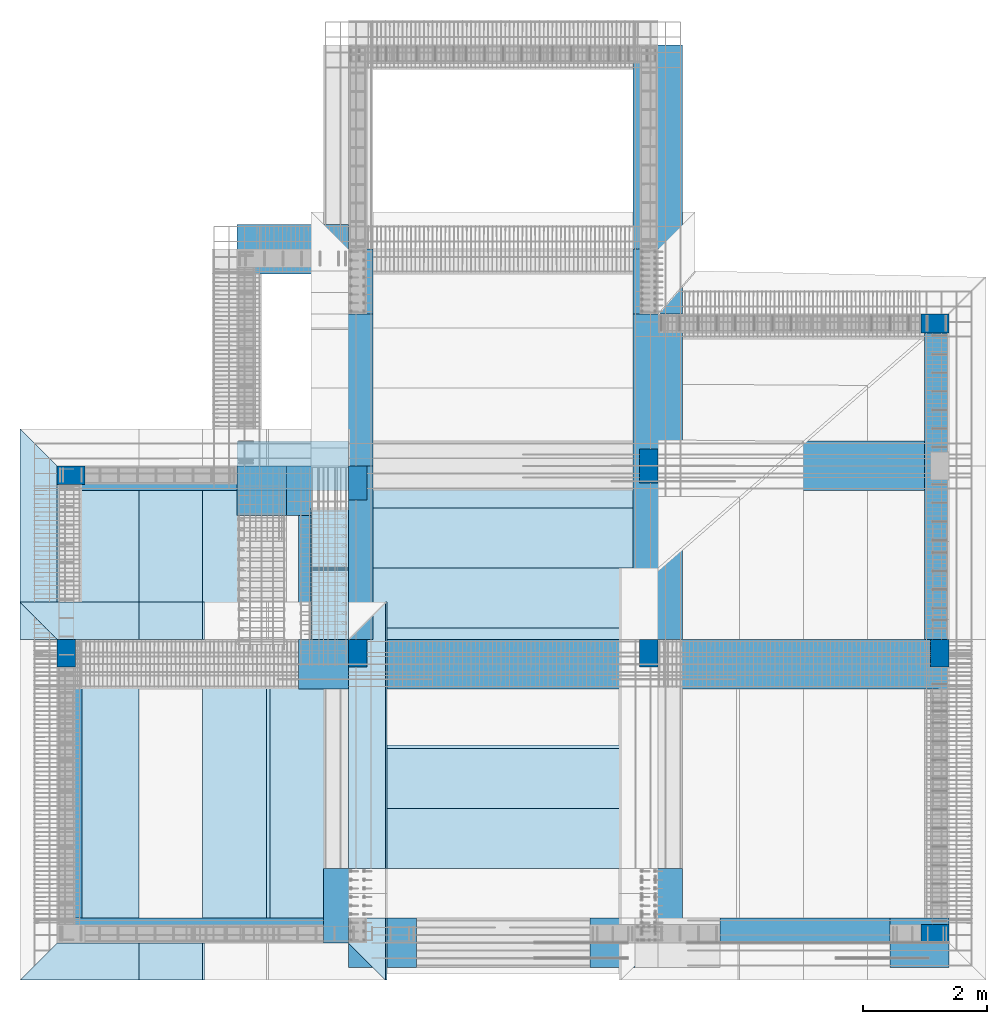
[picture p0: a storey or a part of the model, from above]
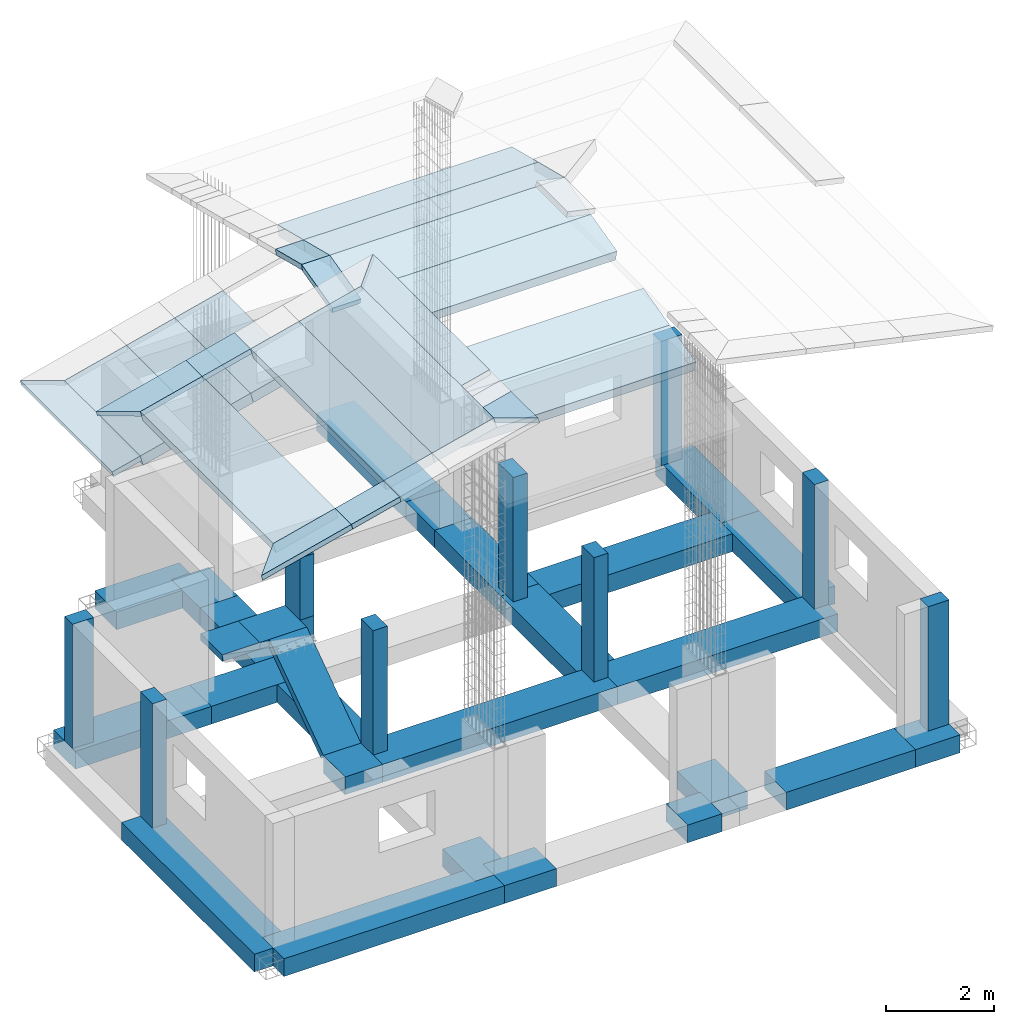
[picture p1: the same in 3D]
Properties of the parts of a building model (IFC4), part 1 of 3

# File
Description: ViewDefinition [CoordinationView]
Made in: IFC file generated by ModeSt (Tecnisoft s.a.s.)

# IfcBuildingStorey (3)
In: Bifamiliare
Name | Elevation (m)
Storey 0 | 0
Storey 1 | 2.8
Storey 2 | 5.95

# IfcBeam: 1 Tr 30x24 (11)
Type - PredefinedType: BEAM; Material: Calcestruzzo
Description: 1 Tr 30x24 - Cemento armato
Pset_BeamCommon - LoadBearing: yes
BaseQuantities - ?: 0.072 m2
Name | In | BaseQuantities, ? (m3) | BaseQuantities, ? (m)
115 | Storey 1 | 0.36 | 5
106 | Storey 1 | 0.3384 | 4.7
106 | Storey 1 | 0.36 | 5
110 | Storey 1 | 0.3384 | 4.7
110 | Storey 1 | 0.36 | 5
120 | Storey 1 | 0.2016 | 2.8
220 | Storey 2 | 0.2016 | 2.8
206 | Storey 2 | 0.3384 | 4.7
206 | Storey 2 | 0.36 | 5
210 | Storey 2 | 0.3384 | 4.7
210 | Storey 2 | 0.36 | 5

# IfcBeam: 10 Scala (6)
Type - PredefinedType: BEAM; Material: Calcestruzzo
Description: 10 Scala - Cemento armato
Pset_BeamCommon - LoadBearing: yes
BaseQuantities - ?: 0.12 m2
Name | In | BaseQuantities, ? (m3) | BaseQuantities, ? (m)
601 | Storey 0 | 0.292957 | 2.44131
602 | Storey 0 | 0.292957 | 2.44131
602 | Storey 0 | 0.096 | 0.8
604 | Storey 1 | 0.096 | 0.8
604 | Storey 1 | 0.305485 | 2.54571
603 | Storey 1 | 0.305485 | 2.54571

# IfcBeam: 11 Pianerottolo (2)
Type - PredefinedType: BEAM; Material: Calcestruzzo
Description: 11 Pianerottolo - Cemento armato
Pset_BeamCommon - LoadBearing: yes
BaseQuantities - ?: 0.15 m2; ?: 0.12 m3; ?: 0.8 m
Name | In
601 | Storey 0
603 | Storey 1

# IfcBeam: 2 Tr 40x24, 102
In: Storey 1
Type - PredefinedType: BEAM; Material: Calcestruzzo
Description: 2 Tr 40x24 - Cemento armato
Pset_BeamCommon - LoadBearing: yes
BaseQuantities - ?: 0.096 m2; ?: 0.48 m3; ?: 5 m

# IfcBeam: 3 Tr 30x44 (34)
Type - PredefinedType: BEAM; Material: Calcestruzzo
Description: 3 Tr 30x44 - Cemento armato
Pset_BeamCommon - LoadBearing: yes
BaseQuantities - ?: 0.132 m2
Name | In | BaseQuantities, ? (m3) | BaseQuantities, ? (m)
122 | Storey 1 | 0.3234 | 2.45
101 | Storey 1 | 0.3696 | 2.8
132 | Storey 1 | 0.363 | 2.75
110 | Storey 1 | 0.2376 | 1.8
123 | Storey 1 | 0.4884 | 3.7
123 | Storey 1 | 0.3696 | 2.8
123 | Storey 1 | 0.3234 | 2.45
122 | Storey 1 | 0.3696 | 2.8
122 | Storey 1 | 0.4884 | 3.7
106 | Storey 1 | 0.3828 | 2.9
2 x 106 | Storey 1 | 0.1056 | 0.8
106 | Storey 1 | 0.0264 | 0.2
202 | Storey 2 | 0.66 | 5
210 | Storey 2 | 0.2376 | 1.8
222 | Storey 2 | 0.3234 | 2.45
227 | Storey 2 | 0.3696 | 2.8
227 | Storey 2 | 0.3234 | 2.45
214 | Storey 2 | 0.6204 | 4.7
215 | Storey 2 | 0.66 | 5
210 | Storey 2 | 0.3828 | 2.9
217 | Storey 2 | 0.3696 | 2.8
217 | Storey 2 | 0.6468 | 4.9
223 | Storey 2 | 0.4884 | 3.7
223 | Storey 2 | 0.3696 | 2.8
223 | Storey 2 | 0.3234 | 2.45
222 | Storey 2 | 0.3696 | 2.8
222 | Storey 2 | 0.4884 | 3.7
206 | Storey 2 | 0.132 | 1
206 | Storey 2 | 0.3828 | 2.9
232 | Storey 2 | 0.6204 | 4.7
227 | Storey 2 | 0.6468 | 4.9
201 | Storey 2 | 0.6204 | 4.7
206 | Storey 2 | 0.1056 | 0.8

# IfcBeam: 4 Tr 30x35 (67)
In: Storey 2
Type - PredefinedType: BEAM; Material: Calcestruzzo
Description: 4 Tr 30x35 - Cemento armato
Pset_BeamCommon - LoadBearing: yes
BaseQuantities - ?: 0.105 m2
Name | BaseQuantities, ? (m3) | BaseQuantities, ? (m)
322 | 0.3885 | 3.7
353 | 0.0855106 | 0.814386
4 x 353 | 0.104994 | 0.999943
4 x 354 | 0.104994 | 0.999943
354 | 0.0854583 | 0.813888
2 x 332 | 0.110717 | 1.05444
2 x 332 | 0.141889 | 1.35133
2 x 368 | 0.110717 | 1.05444
2 x 368 | 0.141889 | 1.35133
2 x 329 | 0.186315 | 1.77442
2 x 329 | 0.145562 | 1.38631
354 | 0.0909248 | 0.86595
354 | 0.0140717 | 0.134016
354 | 0.0985019 | 0.938114
354 | 0.0064947 | 0.0618543
354 | 0.0238137 | 0.226797
353 | 0.0736059 | 0.701009
353 | 0.104997 | 0.999967
2 x 301 | 0.111506 | 1.06197
2 x 301 | 0.142901 | 1.36097
2 x 306 | 0.111506 | 1.06197
2 x 306 | 0.142901 | 1.36097
2 x 310 | 0.111506 | 1.06197
2 x 310 | 0.142901 | 1.36097
2 x 337 | 0.111506 | 1.06197
2 x 337 | 0.142901 | 1.36097
353 | 0.0313907 | 0.298959
354 | 0.0530396 | 0.505139
354 | 0.104997 | 0.999968
317 | 0.5145 | 4.9
384 | 0.294 | 2.8
348 | 0.294 | 2.8
323 | 0.3885 | 3.7
327 | 0.5145 | 4.9
327 | 0.294 | 2.8
327 | 0.25725 | 2.45
314 | 0.4935 | 4.7
354 | 0.0195371 | 0.186068
353 | 0.0194834 | 0.185556
302 | 0.525 | 5
2 x 353 | 0.104997 | 0.999968
354 | 0.0313907 | 0.298959
354 | 0.0205663 | 0.195869
315 | 0.525 | 5
323 | 0.12075 | 1.15
353 | 0.0238137 | 0.226797

# IfcBeam: 5 Tr 80x40 (38)
In: Storey 0
Type - PredefinedType: BEAM; Material: Calcestruzzo
Description: 5 Tr 80x40 - Cemento armato
Pset_BeamCommon - LoadBearing: yes
BaseQuantities - ?: 0.32 m2
Name | BaseQuantities, ? (m3) | BaseQuantities, ? (m)
506 | 1.504 | 4.7
515 | 1.6 | 5
506 | 1.6 | 5
510 | 0.576 | 1.8
523 | 1.184 | 3.7
523 | 0.896 | 2.8
523 | 0.784 | 2.45
522 | 1.184 | 3.7
522 | 0.896 | 2.8
522 | 0.784 | 2.45
501 | 0.896 | 2.8
501 | 0.88 | 2.75
510 | 1.504 | 4.7
510 | 1.6 | 5
522 | 1.056 | 3.3
522 | 0.336 | 1.05
522 | 0.384 | 1.2
514 | 1.504 | 4.7
527 | 0.784 | 2.45
527 | 0.896 | 2.8
527 | 1.568 | 4.9
501 | 0.304 | 0.95
516 | 1.6 | 5
523 | 1.056 | 3.3
523 | 0.336 | 1.05
501 | 0.32 | 1
523 | 0.384 | 1.2
501 | 0.234667 | 0.733334
501 | 0.117333 | 0.366667
515 | 0.576 | 1.8
501 | 0.352 | 1.1
520 | 1.12 | 3.5
510 | 0.928 | 2.9
517 | 0.896 | 2.8
517 | 1.568 | 4.9
501 | 1.504 | 4.7
506 | 1.248 | 3.9
506 | 0.256 | 0.8

# IfcBeam: 6 Tr 20x20 (24)
In: Storey 2
Type - PredefinedType: BEAM; Material: Legname a media elasticità
Description: 6 Tr 20x20 - Legno
Pset_BeamCommon - LoadBearing: yes
BaseQuantities - ?: 0.04 m2
Name | BaseQuantities, ? (m3) | BaseQuantities, ? (m)
349 | 0.112 | 2.8
350 | 0.112 | 2.8
352 | 0.112 | 2.8
307 | 0.2 | 5
305 | 0.2 | 5
304 | 0.2 | 5
303 | 0.2 | 5
309 | 0.2 | 5
311 | 0.2 | 5
312 | 0.2 | 5
313 | 0.2 | 5
328 | 0.0528015 | 1.32004
326 | 0.164 | 4.1
325 | 0.128 | 3.2
324 | 0.092 | 2.3
308 | 0.2 | 5
318 | 0.196 | 4.9
321 | 0.196 | 4.9
326 | 0.196 | 4.9
324 | 0.196 | 4.9
330 | 0.0940035 | 2.35009
331 | 0.135202 | 3.38006
319 | 0.196 | 4.9
325 | 0.196 | 4.9

# IfcColumn: 7 Pil 45x30 (22)
Type - PredefinedType: COLUMN; Material: Calcestruzzo
Description: 7 Pil 45x30 - Cemento armato
Pset_ColumnCommon - LoadBearing: yes
BaseQuantities - ?: 0.135 m2
Name | In | BaseQuantities, ? (m3) | BaseQuantities, ? (m)
5 | Storey 0 | 0.378 | 2.8
4 | Storey 0 | 0.378 | 2.8
10 | Storey 0 | 0.378 | 2.8
6 | Storey 0 | 0.378 | 2.8
3 | Storey 0 | 0.378 | 2.8
3 | Storey 1 | 0.42525 | 3.15
10 | Storey 1 | 0.42525 | 3.15
6 | Storey 1 | 0.42525 | 3.15
5 | Storey 1 | 0.42525 | 3.15
4 | Storey 1 | 0.42525 | 3.15
3 | Storey 2 | 0.2916 | 2.16
3 | Storey 2 | 0.135 | 1
6 | Storey 2 | 0.44685 | 3.31
10 | Storey 2 | 0.44685 | 3.31
8 | Storey 2 | 0.4509 | 3.34
8 | Storey 2 | 0.0792043 | 0.586699
4 | Storey 2 | 0.4509 | 3.34
4 | Storey 2 | 0.0961284 | 0.712062
4 | Storey 2 | 0.0388716 | 0.287938
5 | Storey 2 | 0.54675 | 4.05
5 | Storey 2 | 0.03915 | 0.29
9 | Storey 2 | 0.530104 | 3.9267

# IfcColumn: 8 Pil 30x45 (12)
Type - PredefinedType: COLUMN; Material: Calcestruzzo
Description: 8 Pil 30x45 - Cemento armato
Pset_ColumnCommon - LoadBearing: yes
BaseQuantities - ?: 0.135 m2
Name | In | BaseQuantities, ? (m3) | BaseQuantities, ? (m)
11 | Storey 0 | 0.378 | 2.8
2 | Storey 0 | 0.378 | 2.8
7 | Storey 0 | 0.378 | 2.8
1 | Storey 0 | 0.378 | 2.8
1 | Storey 1 | 0.42525 | 3.15
7 | Storey 1 | 0.42525 | 3.15
11 | Storey 1 | 0.42525 | 3.15
2 | Storey 1 | 0.42525 | 3.15
1 | Storey 2 | 0.4266 | 3.16
7 | Storey 2 | 0.2916 | 2.16
2 | Storey 2 | 0.44685 | 3.31
11 | Storey 2 | 0.44685 | 3.31

# IfcColumn: 9 Pil 55x30 (6)
Type - PredefinedType: COLUMN; Material: Calcestruzzo
Description: 9 Pil 55x30 - Cemento armato
Pset_ColumnCommon - LoadBearing: yes
BaseQuantities - ?: 0.165 m2
Name | In | BaseQuantities, ? (m3) | BaseQuantities, ? (m)
2 x 8 | Storey 0 | 0.231 | 1.4
9 | Storey 0 | 0.462 | 2.8
2 x 8 | Storey 1 | 0.259875 | 1.575
9 | Storey 1 | 0.51975 | 3.15

# IfcReinforcingBar (473)
SteelGrade: B450C
Name | In | NominalDiameter (m) | CrossSectionArea (m2) | BarLength (m)
4 x  | Storey 0 | 0.02 | 0.00031416 | 0.482429
3 x  | Storey 0 | 0.02 | 0.00031416 | 0.466667
4 x  | Storey 0 | 0.02 | 0.00031416 | 0.966667
3 x  | Storey 0 | 0.008 | 0.000050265 | 1.61721
6 x  | Storey 0 | 0.008 | 0.000050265 | 1.46722
 | Storey 0 | 0.02 | 0.00031416 | 0.466668
3 x  | Storey 0 | 0.008 | 0.000050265 | 1.61722
 | Storey 0 | 0.016 | 0.00020106 | 0.485943
 | Storey 0 | 0.016 | 0.00020106 | 0.466668
 | Storey 0 | 0.016 | 0.00020106 | 0.441667
 | Storey 0 | 0.01 | 0.00007854 | 0.777882
4 x  | Storey 0 | 0.02 | 0.00031416 | 0.45
4 x  | Storey 0 | 0.02 | 0.00031416 | 0.95
 | Storey 0 | 0.016 | 0.00020106 | 0.461813
 | Storey 0 | 0.016 | 0.00020106 | 0.459816
 | Storey 0 | 0.016 | 0.00020106 | 0.505553
 | Storey 0 | 0.016 | 0.00020106 | 0.47
 | Storey 0 | 0.016 | 0.00020106 | 0.305649
 | Storey 0 | 0.016 | 0.00020106 | 0.412824
 | Storey 0 | 0.016 | 0.00020106 | 0.39486
 | Storey 0 | 0.016 | 0.00020106 | 0.381667
 | Storey 0 | 0.012 | 0.0001131 | 0.460475
 | Storey 0 | 0.012 | 0.0001131 | 0.435714
 | Storey 0 | 0.012 | 0.0001131 | 0.448098
 | Storey 0 | 0.012 | 0.0001131 | 0.346198
 | Storey 0 | 0.012 | 0.0001131 | 0.381337
 | Storey 0 | 0.012 | 0.0001131 | 0.415977
 | Storey 0 | 0.012 | 0.0001131 | 0.450614
 | Storey 0 | 0.012 | 0.0001131 | 0.485252
 | Storey 0 | 0.012 | 0.0001131 | 0.519893
 | Storey 0 | 0.012 | 0.0001131 | 0.554531
 | Storey 0 | 0.012 | 0.0001131 | 0.589671
 | Storey 0 | 0.012 | 0.0001131 | 0.445714
 | Storey 0 | 0.012 | 0.0001131 | 0.461575
 | Storey 0 | 0.012 | 0.0001131 | 0.453134
 | Storey 0 | 0.012 | 0.0001131 | 0.451867
 | Storey 0 | 0.012 | 0.0001131 | 0.448887
 | Storey 0 | 0.012 | 0.0001131 | 0.564015
 | Storey 0 | 0.012 | 0.0001131 | 0.300458
 | Storey 0 | 0.012 | 0.0001131 | 0.401017
 | Storey 0 | 0.012 | 0.0001131 | 0.406667
 | Storey 0 | 0.012 | 0.0001131 | 0.381667
 | Storey 0 | 0.012 | 0.0001131 | 0.460476
 | Storey 0 | 0.012 | 0.0001131 | 0.423334
 | Storey 0 | 0.012 | 0.0001131 | 0.448097
 | Storey 0 | 0.012 | 0.0001131 | 0.346197
 | Storey 0 | 0.012 | 0.0001131 | 0.370945
 | Storey 0 | 0.012 | 0.0001131 | 0.395191
 | Storey 0 | 0.012 | 0.0001131 | 0.419438
 | Storey 0 | 0.012 | 0.0001131 | 0.443686
 | Storey 0 | 0.012 | 0.0001131 | 0.467933
 | Storey 0 | 0.012 | 0.0001131 | 0.49218
 | Storey 0 | 0.012 | 0.0001131 | 0.516428
 | Storey 0 | 0.012 | 0.0001131 | 0.540674
 | Storey 0 | 0.012 | 0.0001131 | 0.564921
 | Storey 0 | 0.012 | 0.0001131 | 0.58967
13 x  | Storey 0 | 0.012 | 0.0001131 | 3.007
13 x  | Storey 0 | 0.012 | 0.0001131 | 1.08782
5 x  | Storey 0 | 0.012 | 0.0001131 | 1.557
 | Storey 0 | 0.01 | 0.00007854 | 10.5812
 | Storey 0 | 0.01 | 0.00007854 | 4.13121
 | Storey 0 | 0.01 | 0.00007854 | 1.98121
 | Storey 0 | 0.01 | 0.00007854 | 2.93122
2 x  | Storey 0 | 0.016 | 0.00020106 | 1.8
5 x  | Storey 0 | 0.008 | 0.000050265 | 1.48678
 | Storey 0 | 0.01 | 0.00007854 | 5.13121
 | Storey 0 | 0.01 | 0.00007854 | 1.73122
 | Storey 0 | 0.01 | 0.00007854 | 2.63121
3 x  | Storey 0 | 0.016 | 0.00020106 | 1.9
2 x  | Storey 0 | 0.01 | 0.00007854 | 3.73121
 | Storey 0 | 0.01 | 0.00007854 | 8.13122
 | Storey 0 | 0.01 | 0.00007854 | 2.93121
 | Storey 0 | 0.01 | 0.00007854 | 4.43122
 | Storey 0 | 0.01 | 0.00007854 | 3.33122
 | Storey 0 | 0.01 | 0.00007854 | 3.93122
 | Storey 0 | 0.01 | 0.00007854 | 2.23122
 | Storey 0 | 0.01 | 0.00007854 | 5.43122
 | Storey 0 | 0.01 | 0.00007854 | 1.08122
 | Storey 0 | 0.01 | 0.00007854 | 1.73121
 | Storey 0 | 0.01 | 0.00007854 | 1.38122
 | Storey 0 | 0.01 | 0.00007854 | 1.43122
 | Storey 0 | 0.01 | 0.00007854 | 1.16455
 | Storey 0 | 0.01 | 0.00007854 | 6.23121
 | Storey 0 | 0.01 | 0.00007854 | 2.78121
 | Storey 0 | 0.01 | 0.00007854 | 2.68121
7 x  | Storey 2 | 0.02 | 0.00031416 | 1.39754
7 x  | Storey 2 | 0.016 | 0.00020106 | 1.40193
7 x  | Storey 2 | 0.02 | 0.00031416 | 3.6
7 x  | Storey 2 | 0.016 | 0.00020106 | 3.6
4 x  | Storey 2 | 0.02 | 0.00031416 | 3.95
4 x  | Storey 2 | 0.016 | 0.00020106 | 3.95
2 x  | Storey 2 | 0.02 | 0.00031416 | 3.34504
2 x  | Storey 2 | 0.016 | 0.00020106 | 3.34943
14 x  | Storey 2 | 0.008 | 0.000050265 | 1.47881
4 x  | Storey 2 | 0.02 | 0.00031416 | 3.49504
4 x  | Storey 2 | 0.016 | 0.00020106 | 3.49943
 | Storey 2 | 0.008 | 0.000050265 | 0.890039
 | Storey 2 | 0.01 | 0.00007854 | 1.48982
3 x  | Storey 2 | 0.016 | 0.00020106 | 1.24193
3 x  | Storey 2 | 0.016 | 0.00020106 | 3.44
3 x  | Storey 2 | 0.016 | 0.00020106 | 3.79
2 x  | Storey 2 | 0.02 | 0.00031416 | 4.52504
2 x  | Storey 2 | 0.016 | 0.00020106 | 4.52943
 | Storey 2 | 0.008 | 0.000050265 | 0.893239
 | Storey 2 | 0.008 | 0.000050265 | 0.89324
3 x  | Storey 2 | 0.022 | 0.00038013 | 4.03
4 x  | Storey 2 | 0.016 | 0.00020106 | 4.03
 | Storey 2 | 0.02 | 0.00031416 | 2.34504
 | Storey 2 | 0.016 | 0.00020106 | 2.34943
 | Storey 2 | 0.016 | 0.00020106 | 3.80116
 | Storey 2 | 0.016 | 0.00020106 | 3.79718
 | Storey 2 | 0.016 | 0.00020106 | 3.79406
 | Storey 2 | 0.016 | 0.00020106 | 3.79181
 | Storey 2 | 0.016 | 0.00020106 | 3.79045
 | Storey 2 | 0.02 | 0.00031416 | 4.11173
2 x  | Storey 2 | 0.016 | 0.00020106 | 4.11613
2 x  | Storey 2 | 0.008 | 0.000050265 | 1.6788
 | Storey 2 | 0.008 | 0.000050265 | 0.933255
 | Storey 2 | 0.01 | 0.00007854 | 1.68982
 | Storey 2 | 0.01 | 0.00007854 | 0.936286
 | Storey 2 | 0.022 | 0.00038013 | 1.47534
 | Storey 2 | 0.016 | 0.00020106 | 1.48193
 | Storey 2 | 0.022 | 0.00038013 | 3.68
 | Storey 2 | 0.016 | 0.00020106 | 3.68
 | Storey 2 | 0.022 | 0.00038013 | 4.03282
 | Storey 2 | 0.02 | 0.00031416 | 4.11174
 | Storey 2 | 0.008 | 0.000050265 | 0.478429
6 x  | Storey 1 | 0.008 | 0.000050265 | 1.50681
 | Storey 1 | 0.018 | 0.00025447 | 3.95455
 | Storey 1 | 0.012 | 0.0001131 | 3.91455
 | Storey 1 | 0.008 | 0.000050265 | 1.30681
 | Storey 1 | 0.016 | 0.00020106 | 5.26321
 | Storey 1 | 0.014 | 0.00015394 | 5.42321
4 x  | Storey 1 | 0.008 | 0.000050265 | 1.10682
 | Storey 1 | 0.018 | 0.00025447 | 5.42122
2 x  | Storey 1 | 0.016 | 0.00020106 | 10.2064
 | Storey 1 | 0.014 | 0.00015394 | 11.4956
 | Storey 1 | 0.014 | 0.00015394 | 2.5
 | Storey 1 | 0.018 | 0.00025447 | 4.49561
 | Storey 1 | 0.012 | 0.0001131 | 6.51622
 | Storey 1 | 0.018 | 0.00025447 | 2.52121
 | Storey 1 | 0.014 | 0.00015394 | 10.9956
 | Storey 1 | 0.018 | 0.00025447 | 2.49561
 | Storey 1 | 0.012 | 0.0001131 | 3.61621
 | Storey 1 | 0.014 | 0.00015394 | 2
 | Storey 1 | 0.016 | 0.00020106 | 5.26121
 | Storey 1 | 0.014 | 0.00015394 | 5.26121
 | Storey 1 | 0.016 | 0.00020106 | 3.36321
 | Storey 1 | 0.014 | 0.00015394 | 3.52321
 | Storey 1 | 0.018 | 0.00025447 | 10.1212
2 x  | Storey 1 | 0.018 | 0.00025447 | 10.0422
 | Storey 1 | 0.012 | 0.0001131 | 5.07971
 | Storey 1 | 0.012 | 0.0001131 | 5.12622
 | Storey 1 | 0.012 | 0.0001131 | 4.32871
 | Storey 1 | 0.018 | 0.00025447 | 9.77122
 | Storey 1 | 0.014 | 0.00015394 | 9.77122
 | Storey 1 | 0.012 | 0.0001131 | 5.14846
 | Storey 1 | 0.012 | 0.0001131 | 5.33246
 | Storey 1 | 0.012 | 0.0001131 | 3.77246
 | Storey 1 | 0.018 | 0.00025447 | 4.14622
 | Storey 1 | 0.012 | 0.0001131 | 4.10622
9 x  | Storey 2 | 0.008 | 0.000050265 | 1.50681
4 x  | Storey 2 | 0.018 | 0.00025447 | 5.42221
2 x  | Storey 2 | 0.012 | 0.0001131 | 5.38221
2 x  | Storey 2 | 0.018 | 0.00025447 | 5.42321
 | Storey 2 | 0.014 | 0.00015394 | 5.42321
2 x  | Storey 2 | 0.012 | 0.0001131 | 5.38321
2 x  | Storey 2 | 0.008 | 0.000050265 | 1.5068
3 x  | Storey 2 | 0.008 | 0.000050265 | 1.10682
 | Storey 2 | 0.014 | 0.00015394 | 5.42221
2 x  | Storey 2 | 0.016 | 0.00020106 | 10.2074
 | Storey 2 | 0.014 | 0.00015394 | 11.9956
2 x  | Storey 2 | 0.018 | 0.00025447 | 4.49561
2 x  | Storey 2 | 0.014 | 0.00015394 | 2.5
2 x  | Storey 2 | 0.012 | 0.0001131 | 6.51721
 | Storey 2 | 0.014 | 0.00015394 | 11.4956
 | Storey 2 | 0.018 | 0.00025447 | 5.42121
 | Storey 2 | 0.012 | 0.0001131 | 5.38121
 | Storey 2 | 0.018 | 0.00025447 | 8.12321
 | Storey 2 | 0.012 | 0.0001131 | 5.94221
 | Storey 2 | 0.012 | 0.0001131 | 4.70471
 | Storey 2 | 0.016 | 0.00020106 | 3.36321
 | Storey 2 | 0.014 | 0.00015394 | 3.52321
2 x  | Storey 2 | 0.018 | 0.00025447 | 10.1212
 | Storey 2 | 0.012 | 0.0001131 | 5.10371
 | Storey 2 | 0.012 | 0.0001131 | 5.12622
 | Storey 2 | 0.012 | 0.0001131 | 4.25371
 | Storey 2 | 0.014 | 0.00015394 | 10.1212
 | Storey 2 | 0.012 | 0.0001131 | 5.15996
 | Storey 2 | 0.012 | 0.0001131 | 5.29496
 | Storey 2 | 0.012 | 0.0001131 | 4.08496
 | Storey 2 | 0.018 | 0.00025447 | 10.5732
 | Storey 2 | 0.012 | 0.0001131 | 5.96096
 | Storey 2 | 0.012 | 0.0001131 | 5.44496
 | Storey 2 | 0.012 | 0.0001131 | 3.73596
18 x  | Storey 2 | 0.008 | 0.000050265 | 1.32681
 | Storey 2 | 0.018 | 0.00025447 | 5.57513
7 x  | Storey 2 | 0.016 | 0.00020106 | 5.57513
2 x  | Storey 2 | 0.016 | 0.00020106 | 5.42122
 | Storey 2 | 0.016 | 0.00020106 | 5.42321
 | Storey 2 | 0.016 | 0.00020106 | 5.42222
 | Storey 2 | 0.016 | 0.00020106 | 5.42322
 | Storey 2 | 0.016 | 0.00020106 | 5.32121
 | Storey 2 | 0.016 | 0.00020106 | 5.32321
 | Storey 2 | 0.016 | 0.00020106 | 4.52121
 | Storey 2 | 0.016 | 0.00020106 | 4.52221
 | Storey 2 | 0.016 | 0.00020106 | 5.67121
 | Storey 2 | 0.016 | 0.00020106 | 10.5722
 | Storey 2 | 0.016 | 0.00020106 | 10.5732
 | Storey 2 | 0.016 | 0.00020106 | 6.97247
 | Storey 2 | 0.016 | 0.00020106 | 6.74213
 | Storey 2 | 0.018 | 0.00025447 | 5.53911
2 x  | Storey 2 | 0.016 | 0.00020106 | 5.53891
 | Storey 2 | 0.016 | 0.00020106 | 3.67122
2 x  | Storey 2 | 0.016 | 0.00020106 | 3.67221
 | Storey 2 | 0.018 | 0.00025447 | 5
 | Storey 2 | 0.016 | 0.00020106 | 5
 | Storey 2 | 0.018 | 0.00025447 | 2.99238
 | Storey 2 | 0.014 | 0.00015394 | 2.99238
 | Storey 2 | 0.016 | 0.00020106 | 10.4194
 | Storey 2 | 0.016 | 0.00020106 | 4.49985
 | Storey 2 | 0.014 | 0.00015394 | 4.49985
 | Storey 2 | 0.016 | 0.00020106 | 2.29763
 | Storey 2 | 0.014 | 0.00015394 | 2.29763
 | Storey 2 | 0.016 | 0.00020106 | 1.99985
 | Storey 2 | 0.014 | 0.00015394 | 1.99985
 | Storey 2 | 0.016 | 0.00020106 | 4.99238
 | Storey 2 | 0.016 | 0.00020106 | 6.99223
 | Storey 2 | 0.018 | 0.00025447 | 3.5
 | Storey 2 | 0.014 | 0.00015394 | 3.5
 | Storey 2 | 0.016 | 0.00020106 | 10.4246
 | Storey 2 | 0.018 | 0.00025447 | 5.51848
 | Storey 2 | 0.016 | 0.00020106 | 3.67121
11 x  | Storey 0 | 0.008 | 0.000050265 | 2.42679
 | Storey 0 | 0.016 | 0.00020106 | 11.8364
 | Storey 0 | 0.016 | 0.00020106 | 4.83642
3 x  | Storey 0 | 0.016 | 0.00020106 | 2
 | Storey 0 | 0.016 | 0.00020106 | 1.5
 | Storey 0 | 0.016 | 0.00020106 | 3.85163
 | Storey 0 | 0.016 | 0.00020106 | 3.80163
2 x  | Storey 0 | 0.016 | 0.00020106 | 10.8364
 | Storey 0 | 0.016 | 0.00020106 | 2.5
2 x  | Storey 0 | 0.016 | 0.00020106 | 5.83642
2 x  | Storey 0 | 0.016 | 0.00020106 | 9.49561
2 x  | Storey 0 | 0.016 | 0.00020106 | 7.49561
 | Storey 0 | 0.016 | 0.00020106 | 5.92121
 | Storey 0 | 0.016 | 0.00020106 | 8.02121
 | Storey 0 | 0.016 | 0.00020106 | 6.22121
 | Storey 0 | 0.016 | 0.00020106 | 8.92122
 | Storey 0 | 0.016 | 0.00020106 | 4.72121
 | Storey 0 | 0.016 | 0.00020106 | 5.48642
 | Storey 0 | 0.016 | 0.00020106 | 11.2864
 | Storey 0 | 0.016 | 0.00020106 | 5.49561
 | Storey 0 | 0.016 | 0.00020106 | 11.4956
 | Storey 0 | 0.016 | 0.00020106 | 6.49561
 | Storey 0 | 0.016 | 0.00020106 | 11.3712
2 x  | Storey 0 | 0.008 | 0.000050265 | 1.9268
 | Storey 0 | 0.008 | 0.000050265 | 2.32679
 | Storey 0 | 0.014 | 0.00015394 | 3.90992
 | Storey 0 | 0.014 | 0.00015394 | 3.89517
 | Storey 0 | 0.014 | 0.00015394 | 0.833931
 | Storey 0 | 0.014 | 0.00015394 | 3.47578
 | Storey 0 | 0.014 | 0.00015394 | 3.56941
 | Storey 0 | 0.014 | 0.00015394 | 1.28074
2 x  | Storey 1 | 0.008 | 0.000050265 | 1.9268
 | Storey 1 | 0.008 | 0.000050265 | 2.32679
 | Storey 1 | 0.014 | 0.00015394 | 4.04502
 | Storey 1 | 0.014 | 0.00015394 | 4.02817
 | Storey 1 | 0.014 | 0.00015394 | 0.829243
 | Storey 1 | 0.014 | 0.00015394 | 3.56722
 | Storey 1 | 0.014 | 0.00015394 | 3.6688
 | Storey 1 | 0.014 | 0.00015394 | 1.27728

# IfcSlab: 1 Solaio calpestio (19)
Type - PredefinedType: FLOOR; Material: Concrete
Description: 1 Solaio calpestio - Altezza solaio 0.240000 - Spessore cappa 0.040000 -
Pset_SlabCommon - LoadBearing: yes
BaseQuantities - ?: 0.24 m
Name | In | BaseQuantities, ? (m2) | BaseQuantities, ? (m3)
100 | Storey 1 | 8.12 | 1.9488
101 | Storey 1 | 6.3 | 1.512
102 | Storey 1 | 16.5 | 3.96
103 | Storey 1 | 17.5 | 4.2
104 | Storey 1 | 14 | 3.36
105 | Storey 1 | 11.515 | 2.7636
106 | Storey 1 | 13.16 | 3.1584
107 | Storey 1 | 23.03 | 5.5272
108 | Storey 1 | 18.5 | 4.44
109 | Storey 1 | -6 | -1.44
110 | Storey 1 | -23.03 | -5.5272
200 | Storey 2 | -23.03 | -5.5272
201 | Storey 2 | 8.12 | 1.9488
202 | Storey 2 | 18.5 | 4.44
203 | Storey 2 | 14 | 3.36
204 | Storey 2 | 13.16 | 3.1584
205 | Storey 2 | -23.03 | -5.5272
206 | Storey 2 | 11.515 | 2.7636
207 | Storey 2 | 17.5 | 4.2

# IfcSlab: 2 Solaio copertura (30)
In: Storey 0
Type - PredefinedType: FLOOR; Material: Concrete
Description: 2 Solaio copertura - Altezza solaio 0.240000 - Spessore cappa 0.000000 -
Pset_SlabCommon - LoadBearing: yes
BaseQuantities - ?: 0.24 m
Name | BaseQuantities, ? (m2) | BaseQuantities, ? (m3)
301 | -4.85 | -1.164
302 | -4.85 | -1.164
303 | -4.85 | -1.164
304 | -4.85 | -1.164
305 | -6.35 | -1.524
306 | -0.7656 | -0.183744
307 | -1.6684 | -0.400416
308 | -2.5888 | -0.621312
309 | -4.6122 | -1.10693
310 | -2.277 | -0.54648
311 | -2.8325 | -0.6798
312 | -3.7595 | -0.902281
313 | -6.171 | -1.48104
314 | -6.468 | -1.55232
315 | -5.047 | -1.21128
316 | -5.047 | -1.21128
317 | -6.468 | -1.55232
361 | -4.85 | -1.164
362 | -4.85 | -1.164
363 | -4.85 | -1.164
364 | -4.85 | -1.164
365 | -4.85 | -1.164
366 | -6.468 | -1.55232
367 | 5.047 | 1.21128
368 | 5.047 | 1.21128
369 | 6.468 | 1.55232
370 | 3.696 | 0.88704
371 | 2.884 | 0.69216
372 | 2.884 | 0.69216
373 | -3.696 | -0.88704

# IfcSlab: 3 Aggetto di gronda (44)
In: Storey 0
Type - PredefinedType: FLOOR; Material: Concrete
Description: 3 Aggetto di gronda - Altezza solaio 0.120000 - Spessore cappa 0.120000 -
Pset_SlabCommon - LoadBearing: yes
BaseQuantities - ?: 0.12 m
Name | BaseQuantities, ? (m2) | BaseQuantities, ? (m3)
300 | -8.5 | -1.02
318 | 3.085 | 0.3702
319 | -0.600001 | -0.0720001
320 | 3.36 | 0.4032
321 | 0.39 | 0.0468
322 | 0.21 | 0.0252
323 | 0.21 | 0.0252
324 | 0.132 | 0.01584
325 | 0.582 | 0.06984
326 | 0.581999 | 0.0698399
327 | 0.174 | 0.02088
328 | 0.408 | 0.04896
329 | 0.582 | 0.06984
330 | 0.792001 | 0.0950401
331 | 0.618 | 0.07416
332 | 0.618 | 0.07416
333 | 0.972001 | 0.11664
334 | 1.86 | 0.2232
335 | 0.69 | 0.0828
336 | 2.22 | 0.2664
337 | 0.24 | 0.0288
338 | 0.24 | 0.0288
339 | 0.42 | 0.0504
340 | 0.972 | 0.11664
341 | 0.618 | 0.07416
342 | 0.618 | 0.0741601
343 | 0.972 | 0.11664
344 | 3.12 | 0.3744
345 | 1.68 | 0.2016
346 | 1.65 | 0.198
347 | 0.69 | 0.0828
348 | 0.972 | 0.11664
349 | 0.618 | 0.07416
350 | 0.618 | 0.07416
351 | 0.972 | 0.11664
352 | 3.3 | 0.396
353 | 0.972 | 0.11664
354 | 0.618 | 0.07416
355 | 0.618 | 0.07416
356 | 0.972 | 0.11664
357 | 0.42 | 0.0504
358 | 0.24 | 0.0288
359 | 0.24 | 0.0288
360 | 2.4 | 0.288

# IfcSlab: 4 Balconi (4)
Type - PredefinedType: FLOOR; Material: Concrete
Description: 4 Balconi - Altezza solaio 0.200000 - Spessore cappa 0.200000 -
Pset_SlabCommon - LoadBearing: yes
BaseQuantities - ?: 0.2 m
Name | In | BaseQuantities, ? (m2) | BaseQuantities, ? (m3)
112 | Storey 1 | -7 | -1.4
208 | Storey 2 | -4.76 | -0.952
209 | Storey 2 | 8.925 | 1.785
210 | Storey 2 | -18.32 | -3.664

# IfcSlab: 5 Marciapiedi (4)
In: Storey 1
Type - PredefinedType: FLOOR; Material: Concrete
Description: 5 Marciapiedi - Altezza solaio 0.150000 - Spessore cappa 0.150000 -
Pset_SlabCommon - LoadBearing: yes
BaseQuantities - ?: 0.15 m
Name | BaseQuantities, ? (m2) | BaseQuantities, ? (m3)
111 | 6.71 | 1.0065
113 | -7.35 | -1.1025
114 | 8.08 | 1.212
115 | 7.66501 | 1.14975

# IfcWall: 2 Scala (6)
Type - PredefinedType: STANDARD
Description: 2 Scala; Material: Calcestruzzo 0.15 m
Pset_WallCommon - LoadBearing: yes
Name | In | ? (m3)
2 x  | Storey 0 | 2.54141
 | Storey 0 | 0.216
2 x  | Storey 1 | 2.83423
 | Storey 1 | 0.216

# IfcWall: 4 Nuclei (2)
In: Storey 2
Type - PredefinedType: STANDARD
Description: 4 Nuclei; Material: Calcestruzzo 0.3 m
Pset_WallCommon - LoadBearing: yes
BaseQuantities - ?: 1.0436 m3

# IfcWallStandardCase: 1 Pareti (13)
In: Storey 0
Type - PredefinedType: STANDARD
Material: Calcestruzzo 0.3 m
Pset_WallCommon - LoadBearing: yes
BaseQuantities - ?: 2.8 m
Name | Description | BaseQuantities, ? (m2) | BaseQuantities, ? (m3)
121 | Wall number 121 | 0.3 | 0.84
120 | Wall number 120 | 0.285 | 0.798
122 | Wall number 122 | 0.22 | 0.616
119 | Wall number 119 | 0.99 | 2.772
104 | Wall number 104 | 1.41 | 3.948
103 | Wall number 103 | 3.045 | 8.526
118 | Wall number 118 | 1.5 | 4.2
117 | Wall number 117 | 0.54 | 1.512
116 | Wall number 116 | 1.05 | 2.94
115 | Wall number 115 | 0.87 | 2.436
114 | Wall number 114 | 2.31 | 6.468
109 | Wall number 109 | 0.99 | 2.772
123 | Wall number 123 | 1.74 | 4.872

# IfcWallStandardCase: 4 Nuclei (11)
Type - PredefinedType: STANDARD
Material: Calcestruzzo 0.3 m
Pset_WallCommon - LoadBearing: yes
Name | In | Description | BaseQuantities, ? (m2) | BaseQuantities, ? (m3) | BaseQuantities, ? (m)
110 | Storey 0 | Wall number 110 | 0.36 | 1.008 | 2.8
111 | Storey 0 | Wall number 111 | 0.315 | 0.882 | 2.8
107 | Storey 0 | Wall number 107 | 0.36 | 1.008 | 2.8
108 | Storey 0 | Wall number 108 | 0.315 | 0.882 | 2.8
124 | Storey 0 | Wall number 124 | 0.11 | 0.308 | 2.8
211 | Storey 1 | Wall number 211 | 0.315 | 0.99225 | 3.15
210 | Storey 1 | Wall number 210 | 0.36 | 1.134 | 3.15
208 | Storey 1 | Wall number 208 | 0.315 | 0.99225 | 3.15
207 | Storey 1 | Wall number 207 | 0.36 | 1.134 | 3.15
307 | Storey 2 | Wall number 307 | 0.36 | 1.5624 | 4.34
310 | Storey 2 | Wall number 310 | 0.36 | 1.5624 | 4.34

# IfcReinforcingBarType, no part of this type: type
PredefinedType: MAIN; NominalDiameter: 0.02 m; CrossSectionArea: 0.00031416 m2; BarLength: 0.482429 m; Material: Steel

# IfcReinforcingBarType, no part of this type: type
PredefinedType: MAIN; NominalDiameter: 0.02 m; CrossSectionArea: 0.00031416 m2; BarLength: 0.466667 m; Material: Steel

# IfcReinforcingBarType, no part of this type: type
PredefinedType: MAIN; NominalDiameter: 0.02 m; CrossSectionArea: 0.00031416 m2; BarLength: 0.966667 m; Material: Steel

# IfcReinforcingBarType, no part of this type: type
PredefinedType: LIGATURE; NominalDiameter: 0.008 m; CrossSectionArea: 0.000050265 m2; BarLength: 1.61721 m; Material: Steel

# IfcReinforcingBarType, no part of this type: type
PredefinedType: MAIN; NominalDiameter: 0.02 m; CrossSectionArea: 0.00031416 m2; BarLength: 0.482429 m; Material: Steel

# IfcReinforcingBarType, no part of this type: type
PredefinedType: MAIN; NominalDiameter: 0.02 m; CrossSectionArea: 0.00031416 m2; BarLength: 0.466667 m; Material: Steel

# IfcReinforcingBarType, no part of this type: type
PredefinedType: MAIN; NominalDiameter: 0.02 m; CrossSectionArea: 0.00031416 m2; BarLength: 0.966667 m; Material: Steel

# IfcReinforcingBarType, no part of this type: type
PredefinedType: LIGATURE; NominalDiameter: 0.008 m; CrossSectionArea: 0.000050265 m2; BarLength: 1.46722 m; Material: Steel

# IfcReinforcingBarType, no part of this type: type
PredefinedType: MAIN; NominalDiameter: 0.02 m; CrossSectionArea: 0.00031416 m2; BarLength: 0.482429 m; Material: Steel

# IfcReinforcingBarType, no part of this type: type
PredefinedType: MAIN; NominalDiameter: 0.02 m; CrossSectionArea: 0.00031416 m2; BarLength: 0.466668 m; Material: Steel

# IfcReinforcingBarType, no part of this type: type
PredefinedType: MAIN; NominalDiameter: 0.02 m; CrossSectionArea: 0.00031416 m2; BarLength: 0.966667 m; Material: Steel

# IfcReinforcingBarType, no part of this type: type
PredefinedType: LIGATURE; NominalDiameter: 0.008 m; CrossSectionArea: 0.000050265 m2; BarLength: 1.61722 m; Material: Steel

# IfcReinforcingBarType, no part of this type: type
PredefinedType: MAIN; NominalDiameter: 0.02 m; CrossSectionArea: 0.00031416 m2; BarLength: 0.482429 m; Material: Steel

# IfcReinforcingBarType, no part of this type: type
PredefinedType: MAIN; NominalDiameter: 0.02 m; CrossSectionArea: 0.00031416 m2; BarLength: 0.466667 m; Material: Steel

# IfcReinforcingBarType, no part of this type: type
PredefinedType: MAIN; NominalDiameter: 0.02 m; CrossSectionArea: 0.00031416 m2; BarLength: 0.966667 m; Material: Steel

# IfcReinforcingBarType, no part of this type: type
PredefinedType: LIGATURE; NominalDiameter: 0.008 m; CrossSectionArea: 0.000050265 m2; BarLength: 1.46722 m; Material: Steel

# IfcReinforcingBarType, no part of this type: type
PredefinedType: MAIN; NominalDiameter: 0.016 m; CrossSectionArea: 0.00020106 m2; BarLength: 0.485943 m; Material: Steel

# IfcReinforcingBarType, no part of this type: type
PredefinedType: MAIN; NominalDiameter: 0.016 m; CrossSectionArea: 0.00020106 m2; BarLength: 0.466668 m; Material: Steel

# IfcReinforcingBarType, no part of this type: type
PredefinedType: MAIN; NominalDiameter: 0.016 m; CrossSectionArea: 0.00020106 m2; BarLength: 0.441667 m; Material: Steel

# IfcReinforcingBarType, no part of this type: type
PredefinedType: LIGATURE; NominalDiameter: 0.01 m; CrossSectionArea: 0.00007854 m2; BarLength: 0.777882 m; Material: Steel

# IfcReinforcingBarType, no part of this type: type
PredefinedType: MAIN; NominalDiameter: 0.02 m; CrossSectionArea: 0.00031416 m2; BarLength: 0.45 m; Material: Steel

# IfcReinforcingBarType, no part of this type: type
PredefinedType: MAIN; NominalDiameter: 0.02 m; CrossSectionArea: 0.00031416 m2; BarLength: 0.95 m; Material: Steel

# IfcReinforcingBarType, no part of this type: type
PredefinedType: LIGATURE; NominalDiameter: 0.008 m; CrossSectionArea: 0.000050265 m2; BarLength: 1.61721 m; Material: Steel

# IfcReinforcingBarType, no part of this type: type
PredefinedType: MAIN; NominalDiameter: 0.02 m; CrossSectionArea: 0.00031416 m2; BarLength: 0.45 m; Material: Steel

# IfcReinforcingBarType, no part of this type: type
PredefinedType: MAIN; NominalDiameter: 0.02 m; CrossSectionArea: 0.00031416 m2; BarLength: 0.95 m; Material: Steel

# IfcReinforcingBarType, no part of this type: type
PredefinedType: LIGATURE; NominalDiameter: 0.008 m; CrossSectionArea: 0.000050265 m2; BarLength: 1.46722 m; Material: Steel

# IfcReinforcingBarType, no part of this type: type
PredefinedType: MAIN; NominalDiameter: 0.02 m; CrossSectionArea: 0.00031416 m2; BarLength: 0.45 m; Material: Steel

# IfcReinforcingBarType, no part of this type: type
PredefinedType: MAIN; NominalDiameter: 0.02 m; CrossSectionArea: 0.00031416 m2; BarLength: 0.95 m; Material: Steel

# IfcReinforcingBarType, no part of this type: type
PredefinedType: LIGATURE; NominalDiameter: 0.008 m; CrossSectionArea: 0.000050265 m2; BarLength: 1.61722 m; Material: Steel

# IfcReinforcingBarType, no part of this type: type
PredefinedType: MAIN; NominalDiameter: 0.02 m; CrossSectionArea: 0.00031416 m2; BarLength: 0.45 m; Material: Steel

# IfcReinforcingBarType, no part of this type: type
PredefinedType: MAIN; NominalDiameter: 0.02 m; CrossSectionArea: 0.00031416 m2; BarLength: 0.95 m; Material: Steel

# IfcReinforcingBarType, no part of this type: type
PredefinedType: LIGATURE; NominalDiameter: 0.008 m; CrossSectionArea: 0.000050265 m2; BarLength: 1.46722 m; Material: Steel

# IfcReinforcingBarType, no part of this type: type
PredefinedType: MAIN; NominalDiameter: 0.016 m; CrossSectionArea: 0.00020106 m2; BarLength: 0.461813 m; Material: Steel

# IfcReinforcingBarType, no part of this type: type
PredefinedType: MAIN; NominalDiameter: 0.016 m; CrossSectionArea: 0.00020106 m2; BarLength: 0.459816 m; Material: Steel

# IfcReinforcingBarType, no part of this type: type
PredefinedType: MAIN; NominalDiameter: 0.016 m; CrossSectionArea: 0.00020106 m2; BarLength: 0.505553 m; Material: Steel

# IfcReinforcingBarType, no part of this type: type
PredefinedType: MAIN; NominalDiameter: 0.016 m; CrossSectionArea: 0.00020106 m2; BarLength: 0.47 m; Material: Steel

# IfcReinforcingBarType, no part of this type: type
PredefinedType: MAIN; NominalDiameter: 0.016 m; CrossSectionArea: 0.00020106 m2; BarLength: 0.305649 m; Material: Steel

# IfcReinforcingBarType, no part of this type: type
PredefinedType: MAIN; NominalDiameter: 0.016 m; CrossSectionArea: 0.00020106 m2; BarLength: 0.412824 m; Material: Steel

# IfcReinforcingBarType, no part of this type: type
PredefinedType: MAIN; NominalDiameter: 0.016 m; CrossSectionArea: 0.00020106 m2; BarLength: 0.39486 m; Material: Steel

# IfcReinforcingBarType, no part of this type: type
PredefinedType: MAIN; NominalDiameter: 0.016 m; CrossSectionArea: 0.00020106 m2; BarLength: 0.381667 m; Material: Steel

# IfcReinforcingBarType, no part of this type: type
PredefinedType: LIGATURE; NominalDiameter: 0.008 m; CrossSectionArea: 0.000050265 m2; BarLength: 1.61721 m; Material: Steel

# IfcReinforcingBarType, no part of this type: type
PredefinedType: MAIN; NominalDiameter: 0.012 m; CrossSectionArea: 0.0001131 m2; BarLength: 0.460475 m; Material: Steel

# IfcReinforcingBarType, no part of this type: type
PredefinedType: MAIN; NominalDiameter: 0.012 m; CrossSectionArea: 0.0001131 m2; BarLength: 0.435714 m; Material: Steel

# IfcReinforcingBarType, no part of this type: type
PredefinedType: MAIN; NominalDiameter: 0.012 m; CrossSectionArea: 0.0001131 m2; BarLength: 0.448098 m; Material: Steel

# IfcReinforcingBarType, no part of this type: type
PredefinedType: MAIN; NominalDiameter: 0.012 m; CrossSectionArea: 0.0001131 m2; BarLength: 0.346198 m; Material: Steel

# IfcReinforcingBarType, no part of this type: type
PredefinedType: MAIN; NominalDiameter: 0.012 m; CrossSectionArea: 0.0001131 m2; BarLength: 0.381337 m; Material: Steel

# IfcReinforcingBarType, no part of this type: type
PredefinedType: MAIN; NominalDiameter: 0.012 m; CrossSectionArea: 0.0001131 m2; BarLength: 0.415977 m; Material: Steel

# IfcReinforcingBarType, no part of this type: type
PredefinedType: MAIN; NominalDiameter: 0.012 m; CrossSectionArea: 0.0001131 m2; BarLength: 0.450614 m; Material: Steel

# IfcReinforcingBarType, no part of this type: type
PredefinedType: MAIN; NominalDiameter: 0.012 m; CrossSectionArea: 0.0001131 m2; BarLength: 0.485252 m; Material: Steel

# IfcReinforcingBarType, no part of this type: type
PredefinedType: MAIN; NominalDiameter: 0.012 m; CrossSectionArea: 0.0001131 m2; BarLength: 0.519893 m; Material: Steel

# IfcReinforcingBarType, no part of this type: type
PredefinedType: MAIN; NominalDiameter: 0.012 m; CrossSectionArea: 0.0001131 m2; BarLength: 0.554531 m; Material: Steel

# IfcReinforcingBarType, no part of this type: type
PredefinedType: MAIN; NominalDiameter: 0.012 m; CrossSectionArea: 0.0001131 m2; BarLength: 0.589671 m; Material: Steel

# IfcReinforcingBarType, no part of this type: type
PredefinedType: LIGATURE; NominalDiameter: 0.008 m; CrossSectionArea: 0.000050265 m2; BarLength: 1.46722 m; Material: Steel

# IfcReinforcingBarType, no part of this type: type
PredefinedType: MAIN; NominalDiameter: 0.012 m; CrossSectionArea: 0.0001131 m2; BarLength: 0.445714 m; Material: Steel

# IfcReinforcingBarType, no part of this type: type
PredefinedType: MAIN; NominalDiameter: 0.012 m; CrossSectionArea: 0.0001131 m2; BarLength: 0.461575 m; Material: Steel

# IfcReinforcingBarType, no part of this type: type
PredefinedType: MAIN; NominalDiameter: 0.012 m; CrossSectionArea: 0.0001131 m2; BarLength: 0.453134 m; Material: Steel

# IfcReinforcingBarType, no part of this type: type
PredefinedType: MAIN; NominalDiameter: 0.012 m; CrossSectionArea: 0.0001131 m2; BarLength: 0.451867 m; Material: Steel

# IfcReinforcingBarType, no part of this type: type
PredefinedType: MAIN; NominalDiameter: 0.012 m; CrossSectionArea: 0.0001131 m2; BarLength: 0.448887 m; Material: Steel

# IfcReinforcingBarType, no part of this type: type
PredefinedType: MAIN; NominalDiameter: 0.012 m; CrossSectionArea: 0.0001131 m2; BarLength: 0.564015 m; Material: Steel

# IfcReinforcingBarType, no part of this type: type
PredefinedType: MAIN; NominalDiameter: 0.012 m; CrossSectionArea: 0.0001131 m2; BarLength: 0.300458 m; Material: Steel

# IfcReinforcingBarType, no part of this type: type
PredefinedType: MAIN; NominalDiameter: 0.012 m; CrossSectionArea: 0.0001131 m2; BarLength: 0.401017 m; Material: Steel

# IfcReinforcingBarType, no part of this type: type
PredefinedType: MAIN; NominalDiameter: 0.012 m; CrossSectionArea: 0.0001131 m2; BarLength: 0.406667 m; Material: Steel

# IfcReinforcingBarType, no part of this type: type
PredefinedType: MAIN; NominalDiameter: 0.012 m; CrossSectionArea: 0.0001131 m2; BarLength: 0.381667 m; Material: Steel

# IfcReinforcingBarType, no part of this type: type
PredefinedType: LIGATURE; NominalDiameter: 0.008 m; CrossSectionArea: 0.000050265 m2; BarLength: 1.61722 m; Material: Steel

# IfcReinforcingBarType, no part of this type: type
PredefinedType: MAIN; NominalDiameter: 0.012 m; CrossSectionArea: 0.0001131 m2; BarLength: 0.460476 m; Material: Steel

# IfcReinforcingBarType, no part of this type: type
PredefinedType: MAIN; NominalDiameter: 0.012 m; CrossSectionArea: 0.0001131 m2; BarLength: 0.423334 m; Material: Steel

# IfcReinforcingBarType, no part of this type: type
PredefinedType: MAIN; NominalDiameter: 0.012 m; CrossSectionArea: 0.0001131 m2; BarLength: 0.448097 m; Material: Steel

# IfcReinforcingBarType, no part of this type: type
PredefinedType: MAIN; NominalDiameter: 0.012 m; CrossSectionArea: 0.0001131 m2; BarLength: 0.346197 m; Material: Steel

# IfcReinforcingBarType, no part of this type: type
PredefinedType: MAIN; NominalDiameter: 0.012 m; CrossSectionArea: 0.0001131 m2; BarLength: 0.370945 m; Material: Steel

# IfcReinforcingBarType, no part of this type: type
PredefinedType: MAIN; NominalDiameter: 0.012 m; CrossSectionArea: 0.0001131 m2; BarLength: 0.395191 m; Material: Steel

# IfcReinforcingBarType, no part of this type: type
PredefinedType: MAIN; NominalDiameter: 0.012 m; CrossSectionArea: 0.0001131 m2; BarLength: 0.419438 m; Material: Steel

# IfcReinforcingBarType, no part of this type: type
PredefinedType: MAIN; NominalDiameter: 0.012 m; CrossSectionArea: 0.0001131 m2; BarLength: 0.443686 m; Material: Steel

# IfcReinforcingBarType, no part of this type: type
PredefinedType: MAIN; NominalDiameter: 0.012 m; CrossSectionArea: 0.0001131 m2; BarLength: 0.467933 m; Material: Steel

# IfcReinforcingBarType, no part of this type: type
PredefinedType: MAIN; NominalDiameter: 0.012 m; CrossSectionArea: 0.0001131 m2; BarLength: 0.49218 m; Material: Steel

# IfcReinforcingBarType, no part of this type: type
PredefinedType: MAIN; NominalDiameter: 0.012 m; CrossSectionArea: 0.0001131 m2; BarLength: 0.516428 m; Material: Steel

# IfcReinforcingBarType, no part of this type: type
PredefinedType: MAIN; NominalDiameter: 0.012 m; CrossSectionArea: 0.0001131 m2; BarLength: 0.540674 m; Material: Steel

# IfcReinforcingBarType, no part of this type: type
PredefinedType: MAIN; NominalDiameter: 0.012 m; CrossSectionArea: 0.0001131 m2; BarLength: 0.564921 m; Material: Steel

# IfcReinforcingBarType, no part of this type: type
PredefinedType: MAIN; NominalDiameter: 0.012 m; CrossSectionArea: 0.0001131 m2; BarLength: 0.58967 m; Material: Steel

# IfcReinforcingBarType, no part of this type: type
PredefinedType: LIGATURE; NominalDiameter: 0.008 m; CrossSectionArea: 0.000050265 m2; BarLength: 1.46722 m; Material: Steel

# IfcReinforcingBarType, no part of this type: type
PredefinedType: MAIN; NominalDiameter: 0.012 m; CrossSectionArea: 0.0001131 m2; BarLength: 3.007 m; Material: Steel

# IfcReinforcingBarType, no part of this type: type
PredefinedType: MAIN; NominalDiameter: 0.012 m; CrossSectionArea: 0.0001131 m2; BarLength: 1.08782 m; Material: Steel

# IfcReinforcingBarType, no part of this type: type
PredefinedType: MAIN; NominalDiameter: 0.012 m; CrossSectionArea: 0.0001131 m2; BarLength: 1.557 m; Material: Steel

# IfcReinforcingBarType, no part of this type: type
PredefinedType: LIGATURE; NominalDiameter: 0.01 m; CrossSectionArea: 0.00007854 m2; BarLength: 10.5812 m; Material: Steel

# IfcReinforcingBarType, no part of this type: type
PredefinedType: LIGATURE; NominalDiameter: 0.01 m; CrossSectionArea: 0.00007854 m2; BarLength: 4.13121 m; Material: Steel

# IfcReinforcingBarType, no part of this type: type
PredefinedType: LIGATURE; NominalDiameter: 0.01 m; CrossSectionArea: 0.00007854 m2; BarLength: 1.98121 m; Material: Steel

# IfcReinforcingBarType, no part of this type: type
PredefinedType: LIGATURE; NominalDiameter: 0.01 m; CrossSectionArea: 0.00007854 m2; BarLength: 2.93122 m; Material: Steel

# IfcReinforcingBarType, no part of this type: type
PredefinedType: MAIN; NominalDiameter: 0.016 m; CrossSectionArea: 0.00020106 m2; BarLength: 1.8 m; Material: Steel

# IfcReinforcingBarType, no part of this type: type
PredefinedType: LIGATURE; NominalDiameter: 0.008 m; CrossSectionArea: 0.000050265 m2; BarLength: 1.48678 m; Material: Steel

# IfcReinforcingBarType, no part of this type: type
PredefinedType: MAIN; NominalDiameter: 0.012 m; CrossSectionArea: 0.0001131 m2; BarLength: 3.007 m; Material: Steel

# IfcReinforcingBarType, no part of this type: type
PredefinedType: MAIN; NominalDiameter: 0.012 m; CrossSectionArea: 0.0001131 m2; BarLength: 1.08782 m; Material: Steel

# IfcReinforcingBarType, no part of this type: type
PredefinedType: MAIN; NominalDiameter: 0.012 m; CrossSectionArea: 0.0001131 m2; BarLength: 1.557 m; Material: Steel

# IfcReinforcingBarType, no part of this type: type
PredefinedType: LIGATURE; NominalDiameter: 0.01 m; CrossSectionArea: 0.00007854 m2; BarLength: 5.13121 m; Material: Steel

# IfcReinforcingBarType, no part of this type: type
PredefinedType: LIGATURE; NominalDiameter: 0.01 m; CrossSectionArea: 0.00007854 m2; BarLength: 1.73122 m; Material: Steel

# IfcReinforcingBarType, no part of this type: type
PredefinedType: LIGATURE; NominalDiameter: 0.01 m; CrossSectionArea: 0.00007854 m2; BarLength: 2.63121 m; Material: Steel

# IfcReinforcingBarType, no part of this type: type
PredefinedType: MAIN; NominalDiameter: 0.016 m; CrossSectionArea: 0.00020106 m2; BarLength: 1.9 m; Material: Steel

# IfcReinforcingBarType, no part of this type: type
PredefinedType: LIGATURE; NominalDiameter: 0.008 m; CrossSectionArea: 0.000050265 m2; BarLength: 1.48678 m; Material: Steel

# IfcReinforcingBarType, no part of this type: type
PredefinedType: MAIN; NominalDiameter: 0.012 m; CrossSectionArea: 0.0001131 m2; BarLength: 3.007 m; Material: Steel

# IfcReinforcingBarType, no part of this type: type
PredefinedType: MAIN; NominalDiameter: 0.012 m; CrossSectionArea: 0.0001131 m2; BarLength: 1.08782 m; Material: Steel

# IfcReinforcingBarType, no part of this type: type
PredefinedType: LIGATURE; NominalDiameter: 0.01 m; CrossSectionArea: 0.00007854 m2; BarLength: 3.73121 m; Material: Steel

# IfcReinforcingBarType, no part of this type: type
PredefinedType: MAIN; NominalDiameter: 0.012 m; CrossSectionArea: 0.0001131 m2; BarLength: 3.007 m; Material: Steel

# IfcReinforcingBarType, no part of this type: type
PredefinedType: MAIN; NominalDiameter: 0.012 m; CrossSectionArea: 0.0001131 m2; BarLength: 1.08782 m; Material: Steel

# IfcReinforcingBarType, no part of this type: type
PredefinedType: MAIN; NominalDiameter: 0.012 m; CrossSectionArea: 0.0001131 m2; BarLength: 1.557 m; Material: Steel

# IfcReinforcingBarType, no part of this type: type
PredefinedType: LIGATURE; NominalDiameter: 0.01 m; CrossSectionArea: 0.00007854 m2; BarLength: 8.13122 m; Material: Steel

# IfcReinforcingBarType, no part of this type: type
PredefinedType: LIGATURE; NominalDiameter: 0.01 m; CrossSectionArea: 0.00007854 m2; BarLength: 2.93121 m; Material: Steel

# IfcReinforcingBarType, no part of this type: type
PredefinedType: LIGATURE; NominalDiameter: 0.01 m; CrossSectionArea: 0.00007854 m2; BarLength: 4.43122 m; Material: Steel

# IfcReinforcingBarType, no part of this type: type
PredefinedType: MAIN; NominalDiameter: 0.016 m; CrossSectionArea: 0.00020106 m2; BarLength: 1.9 m; Material: Steel

# IfcReinforcingBarType, no part of this type: type
PredefinedType: LIGATURE; NominalDiameter: 0.008 m; CrossSectionArea: 0.000050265 m2; BarLength: 1.48678 m; Material: Steel

# IfcReinforcingBarType, no part of this type: type
PredefinedType: MAIN; NominalDiameter: 0.012 m; CrossSectionArea: 0.0001131 m2; BarLength: 3.007 m; Material: Steel

# IfcReinforcingBarType, no part of this type: type
PredefinedType: MAIN; NominalDiameter: 0.012 m; CrossSectionArea: 0.0001131 m2; BarLength: 1.08782 m; Material: Steel

# IfcReinforcingBarType, no part of this type: type
PredefinedType: LIGATURE; NominalDiameter: 0.01 m; CrossSectionArea: 0.00007854 m2; BarLength: 3.33122 m; Material: Steel

# IfcReinforcingBarType, no part of this type: type
PredefinedType: MAIN; NominalDiameter: 0.012 m; CrossSectionArea: 0.0001131 m2; BarLength: 3.007 m; Material: Steel

# IfcReinforcingBarType, no part of this type: type
PredefinedType: MAIN; NominalDiameter: 0.012 m; CrossSectionArea: 0.0001131 m2; BarLength: 1.08782 m; Material: Steel

# IfcReinforcingBarType, no part of this type: type
PredefinedType: LIGATURE; NominalDiameter: 0.01 m; CrossSectionArea: 0.00007854 m2; BarLength: 3.93122 m; Material: Steel

# IfcReinforcingBarType, no part of this type: type
PredefinedType: MAIN; NominalDiameter: 0.012 m; CrossSectionArea: 0.0001131 m2; BarLength: 3.007 m; Material: Steel

# IfcReinforcingBarType, no part of this type: type
PredefinedType: MAIN; NominalDiameter: 0.012 m; CrossSectionArea: 0.0001131 m2; BarLength: 1.08782 m; Material: Steel

# IfcReinforcingBarType, no part of this type: type
PredefinedType: LIGATURE; NominalDiameter: 0.01 m; CrossSectionArea: 0.00007854 m2; BarLength: 2.23122 m; Material: Steel

# IfcReinforcingBarType, no part of this type: type
PredefinedType: MAIN; NominalDiameter: 0.012 m; CrossSectionArea: 0.0001131 m2; BarLength: 3.007 m; Material: Steel

# IfcReinforcingBarType, no part of this type: type
PredefinedType: MAIN; NominalDiameter: 0.012 m; CrossSectionArea: 0.0001131 m2; BarLength: 1.08782 m; Material: Steel

# IfcReinforcingBarType, no part of this type: type
PredefinedType: MAIN; NominalDiameter: 0.012 m; CrossSectionArea: 0.0001131 m2; BarLength: 1.557 m; Material: Steel

# IfcReinforcingBarType, no part of this type: type
PredefinedType: LIGATURE; NominalDiameter: 0.01 m; CrossSectionArea: 0.00007854 m2; BarLength: 5.43122 m; Material: Steel

# IfcReinforcingBarType, no part of this type: type
PredefinedType: LIGATURE; NominalDiameter: 0.01 m; CrossSectionArea: 0.00007854 m2; BarLength: 1.08122 m; Material: Steel

# IfcReinforcingBarType, no part of this type: type
PredefinedType: LIGATURE; NominalDiameter: 0.01 m; CrossSectionArea: 0.00007854 m2; BarLength: 1.73121 m; Material: Steel

# IfcReinforcingBarType, no part of this type: type
PredefinedType: MAIN; NominalDiameter: 0.016 m; CrossSectionArea: 0.00020106 m2; BarLength: 1.8 m; Material: Steel

# IfcReinforcingBarType, no part of this type: type
PredefinedType: LIGATURE; NominalDiameter: 0.008 m; CrossSectionArea: 0.000050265 m2; BarLength: 1.48678 m; Material: Steel

# IfcReinforcingBarType, no part of this type: type
PredefinedType: MAIN; NominalDiameter: 0.012 m; CrossSectionArea: 0.0001131 m2; BarLength: 3.007 m; Material: Steel

# IfcReinforcingBarType, no part of this type: type
PredefinedType: MAIN; NominalDiameter: 0.012 m; CrossSectionArea: 0.0001131 m2; BarLength: 1.08782 m; Material: Steel

# IfcReinforcingBarType, no part of this type: type
PredefinedType: LIGATURE; NominalDiameter: 0.01 m; CrossSectionArea: 0.00007854 m2; BarLength: 3.73121 m; Material: Steel

# IfcReinforcingBarType, no part of this type: type
PredefinedType: MAIN; NominalDiameter: 0.012 m; CrossSectionArea: 0.0001131 m2; BarLength: 3.007 m; Material: Steel

# IfcReinforcingBarType, no part of this type: type
PredefinedType: MAIN; NominalDiameter: 0.012 m; CrossSectionArea: 0.0001131 m2; BarLength: 1.08782 m; Material: Steel

# IfcReinforcingBarType, no part of this type: type
PredefinedType: LIGATURE; NominalDiameter: 0.01 m; CrossSectionArea: 0.00007854 m2; BarLength: 1.38122 m; Material: Steel

# IfcReinforcingBarType, no part of this type: type
PredefinedType: MAIN; NominalDiameter: 0.012 m; CrossSectionArea: 0.0001131 m2; BarLength: 3.007 m; Material: Steel

# IfcReinforcingBarType, no part of this type: type
PredefinedType: MAIN; NominalDiameter: 0.012 m; CrossSectionArea: 0.0001131 m2; BarLength: 1.08782 m; Material: Steel

# IfcReinforcingBarType, no part of this type: type
PredefinedType: LIGATURE; NominalDiameter: 0.01 m; CrossSectionArea: 0.00007854 m2; BarLength: 1.43122 m; Material: Steel

# IfcReinforcingBarType, no part of this type: type
PredefinedType: MAIN; NominalDiameter: 0.012 m; CrossSectionArea: 0.0001131 m2; BarLength: 3.007 m; Material: Steel

# IfcReinforcingBarType, no part of this type: type
PredefinedType: MAIN; NominalDiameter: 0.012 m; CrossSectionArea: 0.0001131 m2; BarLength: 1.08782 m; Material: Steel

# IfcReinforcingBarType, no part of this type: type
PredefinedType: LIGATURE; NominalDiameter: 0.01 m; CrossSectionArea: 0.00007854 m2; BarLength: 1.16455 m; Material: Steel

# IfcReinforcingBarType, no part of this type: type
PredefinedType: MAIN; NominalDiameter: 0.012 m; CrossSectionArea: 0.0001131 m2; BarLength: 3.007 m; Material: Steel

# IfcReinforcingBarType, no part of this type: type
PredefinedType: MAIN; NominalDiameter: 0.012 m; CrossSectionArea: 0.0001131 m2; BarLength: 1.08782 m; Material: Steel

# IfcReinforcingBarType, no part of this type: type
PredefinedType: MAIN; NominalDiameter: 0.012 m; CrossSectionArea: 0.0001131 m2; BarLength: 1.557 m; Material: Steel

# IfcReinforcingBarType, no part of this type: type
PredefinedType: LIGATURE; NominalDiameter: 0.01 m; CrossSectionArea: 0.00007854 m2; BarLength: 6.23121 m; Material: Steel

# IfcReinforcingBarType, no part of this type: type
PredefinedType: LIGATURE; NominalDiameter: 0.01 m; CrossSectionArea: 0.00007854 m2; BarLength: 2.78121 m; Material: Steel

# IfcReinforcingBarType, no part of this type: type
PredefinedType: LIGATURE; NominalDiameter: 0.01 m; CrossSectionArea: 0.00007854 m2; BarLength: 2.68121 m; Material: Steel

# IfcReinforcingBarType, no part of this type: type
PredefinedType: MAIN; NominalDiameter: 0.016 m; CrossSectionArea: 0.00020106 m2; BarLength: 1.9 m; Material: Steel

# IfcReinforcingBarType, no part of this type: type
PredefinedType: LIGATURE; NominalDiameter: 0.008 m; CrossSectionArea: 0.000050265 m2; BarLength: 1.48678 m; Material: Steel

# IfcReinforcingBarType, no part of this type: type
PredefinedType: MAIN; NominalDiameter: 0.02 m; CrossSectionArea: 0.00031416 m2; BarLength: 1.39754 m; Material: Steel

# IfcReinforcingBarType, no part of this type: type
PredefinedType: MAIN; NominalDiameter: 0.016 m; CrossSectionArea: 0.00020106 m2; BarLength: 1.40193 m; Material: Steel

# IfcReinforcingBarType, no part of this type: type
PredefinedType: MAIN; NominalDiameter: 0.02 m; CrossSectionArea: 0.00031416 m2; BarLength: 3.6 m; Material: Steel

# IfcReinforcingBarType, no part of this type: type
PredefinedType: MAIN; NominalDiameter: 0.016 m; CrossSectionArea: 0.00020106 m2; BarLength: 3.6 m; Material: Steel

# IfcReinforcingBarType, no part of this type: type
PredefinedType: MAIN; NominalDiameter: 0.02 m; CrossSectionArea: 0.00031416 m2; BarLength: 3.95 m; Material: Steel

# IfcReinforcingBarType, no part of this type: type
PredefinedType: MAIN; NominalDiameter: 0.016 m; CrossSectionArea: 0.00020106 m2; BarLength: 3.95 m; Material: Steel

# IfcReinforcingBarType, no part of this type: type
PredefinedType: MAIN; NominalDiameter: 0.02 m; CrossSectionArea: 0.00031416 m2; BarLength: 3.34504 m; Material: Steel

# IfcReinforcingBarType, no part of this type: type
PredefinedType: MAIN; NominalDiameter: 0.016 m; CrossSectionArea: 0.00020106 m2; BarLength: 3.34943 m; Material: Steel

# IfcReinforcingBarType, no part of this type: type
PredefinedType: LIGATURE; NominalDiameter: 0.008 m; CrossSectionArea: 0.000050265 m2; BarLength: 1.47881 m; Material: Steel

# IfcReinforcingBarType, no part of this type: type
PredefinedType: MAIN; NominalDiameter: 0.02 m; CrossSectionArea: 0.00031416 m2; BarLength: 1.39754 m; Material: Steel

# IfcReinforcingBarType, no part of this type: type
PredefinedType: MAIN; NominalDiameter: 0.016 m; CrossSectionArea: 0.00020106 m2; BarLength: 1.40193 m; Material: Steel

# IfcReinforcingBarType, no part of this type: type
PredefinedType: MAIN; NominalDiameter: 0.02 m; CrossSectionArea: 0.00031416 m2; BarLength: 3.6 m; Material: Steel

# IfcReinforcingBarType, no part of this type: type
PredefinedType: MAIN; NominalDiameter: 0.016 m; CrossSectionArea: 0.00020106 m2; BarLength: 3.6 m; Material: Steel

# IfcReinforcingBarType, no part of this type: type
PredefinedType: MAIN; NominalDiameter: 0.02 m; CrossSectionArea: 0.00031416 m2; BarLength: 3.95 m; Material: Steel

# IfcReinforcingBarType, no part of this type: type
PredefinedType: MAIN; NominalDiameter: 0.016 m; CrossSectionArea: 0.00020106 m2; BarLength: 3.95 m; Material: Steel

# IfcReinforcingBarType, no part of this type: type
PredefinedType: MAIN; NominalDiameter: 0.02 m; CrossSectionArea: 0.00031416 m2; BarLength: 3.49504 m; Material: Steel

# IfcReinforcingBarType, no part of this type: type
PredefinedType: MAIN; NominalDiameter: 0.016 m; CrossSectionArea: 0.00020106 m2; BarLength: 3.49943 m; Material: Steel

# IfcReinforcingBarType, no part of this type: type
PredefinedType: LIGATURE; NominalDiameter: 0.008 m; CrossSectionArea: 0.000050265 m2; BarLength: 1.47881 m; Material: Steel

# IfcReinforcingBarType, no part of this type: type
PredefinedType: MAIN; NominalDiameter: 0.02 m; CrossSectionArea: 0.00031416 m2; BarLength: 1.39754 m; Material: Steel

# IfcReinforcingBarType, no part of this type: type
PredefinedType: MAIN; NominalDiameter: 0.016 m; CrossSectionArea: 0.00020106 m2; BarLength: 1.40193 m; Material: Steel

# IfcReinforcingBarType, no part of this type: type
PredefinedType: MAIN; NominalDiameter: 0.02 m; CrossSectionArea: 0.00031416 m2; BarLength: 3.6 m; Material: Steel

# IfcReinforcingBarType, no part of this type: type
PredefinedType: MAIN; NominalDiameter: 0.016 m; CrossSectionArea: 0.00020106 m2; BarLength: 3.6 m; Material: Steel

# IfcReinforcingBarType, no part of this type: type
PredefinedType: MAIN; NominalDiameter: 0.02 m; CrossSectionArea: 0.00031416 m2; BarLength: 3.95 m; Material: Steel

# IfcReinforcingBarType, no part of this type: type
PredefinedType: MAIN; NominalDiameter: 0.016 m; CrossSectionArea: 0.00020106 m2; BarLength: 3.95 m; Material: Steel

# IfcReinforcingBarType, no part of this type: type
PredefinedType: MAIN; NominalDiameter: 0.02 m; CrossSectionArea: 0.00031416 m2; BarLength: 3.34504 m; Material: Steel

# IfcReinforcingBarType, no part of this type: type
PredefinedType: MAIN; NominalDiameter: 0.016 m; CrossSectionArea: 0.00020106 m2; BarLength: 3.34943 m; Material: Steel

# IfcReinforcingBarType, no part of this type: type
PredefinedType: LIGATURE; NominalDiameter: 0.008 m; CrossSectionArea: 0.000050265 m2; BarLength: 1.47881 m; Material: Steel

# IfcReinforcingBarType, no part of this type: type
PredefinedType: LIGATURE; NominalDiameter: 0.008 m; CrossSectionArea: 0.000050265 m2; BarLength: 1.47881 m; Material: Steel

# IfcReinforcingBarType, no part of this type: type
PredefinedType: LIGATURE; NominalDiameter: 0.008 m; CrossSectionArea: 0.000050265 m2; BarLength: 0.890039 m; Material: Steel

# IfcReinforcingBarType, no part of this type: type
PredefinedType: LIGATURE; NominalDiameter: 0.01 m; CrossSectionArea: 0.00007854 m2; BarLength: 1.48982 m; Material: Steel

# IfcReinforcingBarType, no part of this type: type
PredefinedType: MAIN; NominalDiameter: 0.016 m; CrossSectionArea: 0.00020106 m2; BarLength: 1.24193 m; Material: Steel

# IfcReinforcingBarType, no part of this type: type
PredefinedType: MAIN; NominalDiameter: 0.016 m; CrossSectionArea: 0.00020106 m2; BarLength: 3.44 m; Material: Steel

# IfcReinforcingBarType, no part of this type: type
PredefinedType: MAIN; NominalDiameter: 0.016 m; CrossSectionArea: 0.00020106 m2; BarLength: 3.79 m; Material: Steel

# IfcReinforcingBarType, no part of this type: type
PredefinedType: MAIN; NominalDiameter: 0.02 m; CrossSectionArea: 0.00031416 m2; BarLength: 4.52504 m; Material: Steel

# IfcReinforcingBarType, no part of this type: type
PredefinedType: MAIN; NominalDiameter: 0.016 m; CrossSectionArea: 0.00020106 m2; BarLength: 4.52943 m; Material: Steel

# IfcReinforcingBarType, no part of this type: type
PredefinedType: LIGATURE; NominalDiameter: 0.008 m; CrossSectionArea: 0.000050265 m2; BarLength: 1.47881 m; Material: Steel

# IfcReinforcingBarType, no part of this type: type
PredefinedType: LIGATURE; NominalDiameter: 0.008 m; CrossSectionArea: 0.000050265 m2; BarLength: 0.893239 m; Material: Steel

# IfcReinforcingBarType, no part of this type: type
PredefinedType: LIGATURE; NominalDiameter: 0.008 m; CrossSectionArea: 0.000050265 m2; BarLength: 1.47881 m; Material: Steel

# IfcReinforcingBarType, no part of this type: type
PredefinedType: MAIN; NominalDiameter: 0.016 m; CrossSectionArea: 0.00020106 m2; BarLength: 1.24193 m; Material: Steel

# IfcReinforcingBarType, no part of this type: type
PredefinedType: MAIN; NominalDiameter: 0.016 m; CrossSectionArea: 0.00020106 m2; BarLength: 3.44 m; Material: Steel

# IfcReinforcingBarType, no part of this type: type
PredefinedType: MAIN; NominalDiameter: 0.016 m; CrossSectionArea: 0.00020106 m2; BarLength: 3.79 m; Material: Steel

# IfcReinforcingBarType, no part of this type: type
PredefinedType: MAIN; NominalDiameter: 0.02 m; CrossSectionArea: 0.00031416 m2; BarLength: 4.52504 m; Material: Steel

# IfcReinforcingBarType, no part of this type: type
PredefinedType: MAIN; NominalDiameter: 0.016 m; CrossSectionArea: 0.00020106 m2; BarLength: 4.52943 m; Material: Steel

# IfcReinforcingBarType, no part of this type: type
PredefinedType: LIGATURE; NominalDiameter: 0.008 m; CrossSectionArea: 0.000050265 m2; BarLength: 1.47881 m; Material: Steel

# IfcReinforcingBarType, no part of this type: type
PredefinedType: LIGATURE; NominalDiameter: 0.008 m; CrossSectionArea: 0.000050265 m2; BarLength: 0.89324 m; Material: Steel

# IfcReinforcingBarType, no part of this type: type
PredefinedType: LIGATURE; NominalDiameter: 0.008 m; CrossSectionArea: 0.000050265 m2; BarLength: 1.47881 m; Material: Steel

# IfcReinforcingBarType, no part of this type: type
PredefinedType: MAIN; NominalDiameter: 0.02 m; CrossSectionArea: 0.00031416 m2; BarLength: 1.39754 m; Material: Steel

# IfcReinforcingBarType, no part of this type: type
PredefinedType: MAIN; NominalDiameter: 0.016 m; CrossSectionArea: 0.00020106 m2; BarLength: 1.40193 m; Material: Steel

# IfcReinforcingBarType, no part of this type: type
PredefinedType: MAIN; NominalDiameter: 0.02 m; CrossSectionArea: 0.00031416 m2; BarLength: 3.6 m; Material: Steel

# IfcReinforcingBarType, no part of this type: type
PredefinedType: MAIN; NominalDiameter: 0.016 m; CrossSectionArea: 0.00020106 m2; BarLength: 3.6 m; Material: Steel

# IfcReinforcingBarType, no part of this type: type
PredefinedType: MAIN; NominalDiameter: 0.022 m; CrossSectionArea: 0.00038013 m2; BarLength: 4.03 m; Material: Steel

# IfcReinforcingBarType, no part of this type: type
PredefinedType: MAIN; NominalDiameter: 0.016 m; CrossSectionArea: 0.00020106 m2; BarLength: 4.03 m; Material: Steel

# IfcReinforcingBarType, no part of this type: type
PredefinedType: MAIN; NominalDiameter: 0.02 m; CrossSectionArea: 0.00031416 m2; BarLength: 3.49504 m; Material: Steel

# IfcReinforcingBarType, no part of this type: type
PredefinedType: MAIN; NominalDiameter: 0.016 m; CrossSectionArea: 0.00020106 m2; BarLength: 3.49943 m; Material: Steel

# IfcReinforcingBarType, no part of this type: type
PredefinedType: LIGATURE; NominalDiameter: 0.008 m; CrossSectionArea: 0.000050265 m2; BarLength: 1.47881 m; Material: Steel

# IfcReinforcingBarType, no part of this type: type
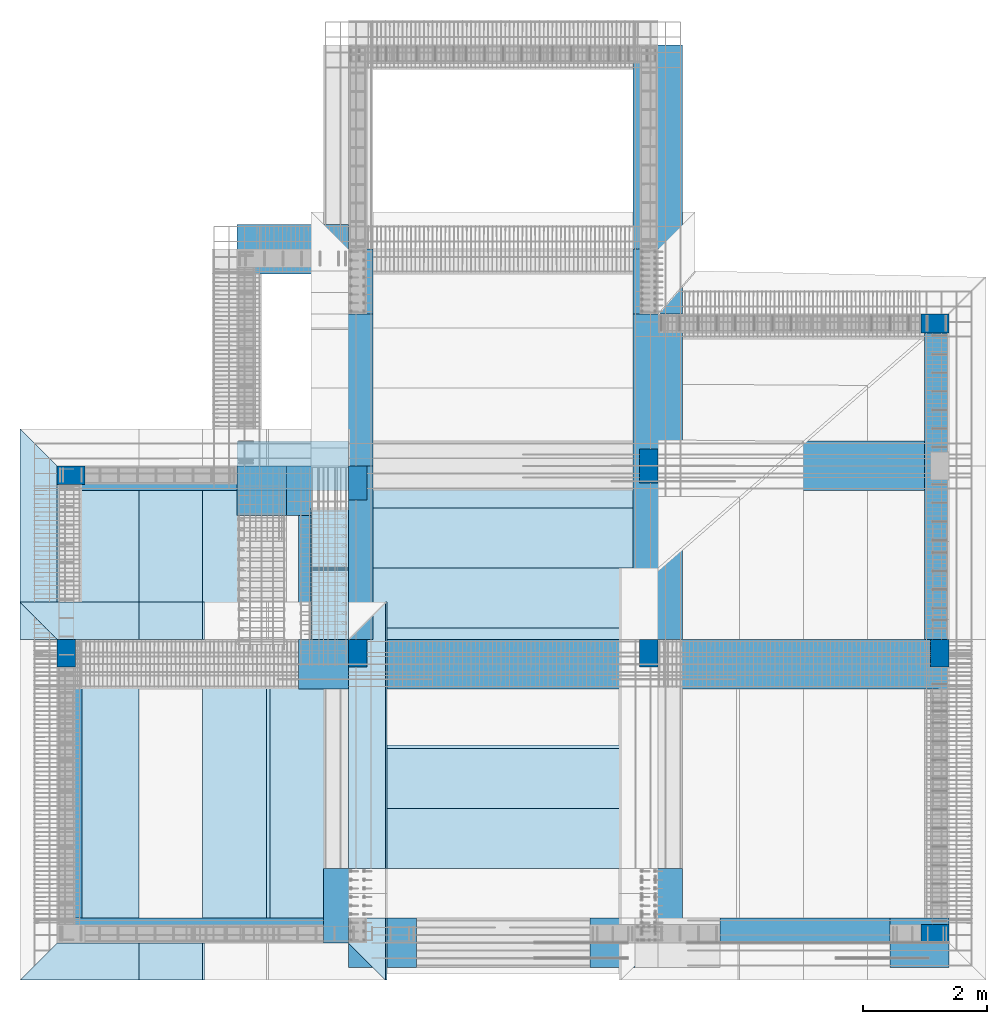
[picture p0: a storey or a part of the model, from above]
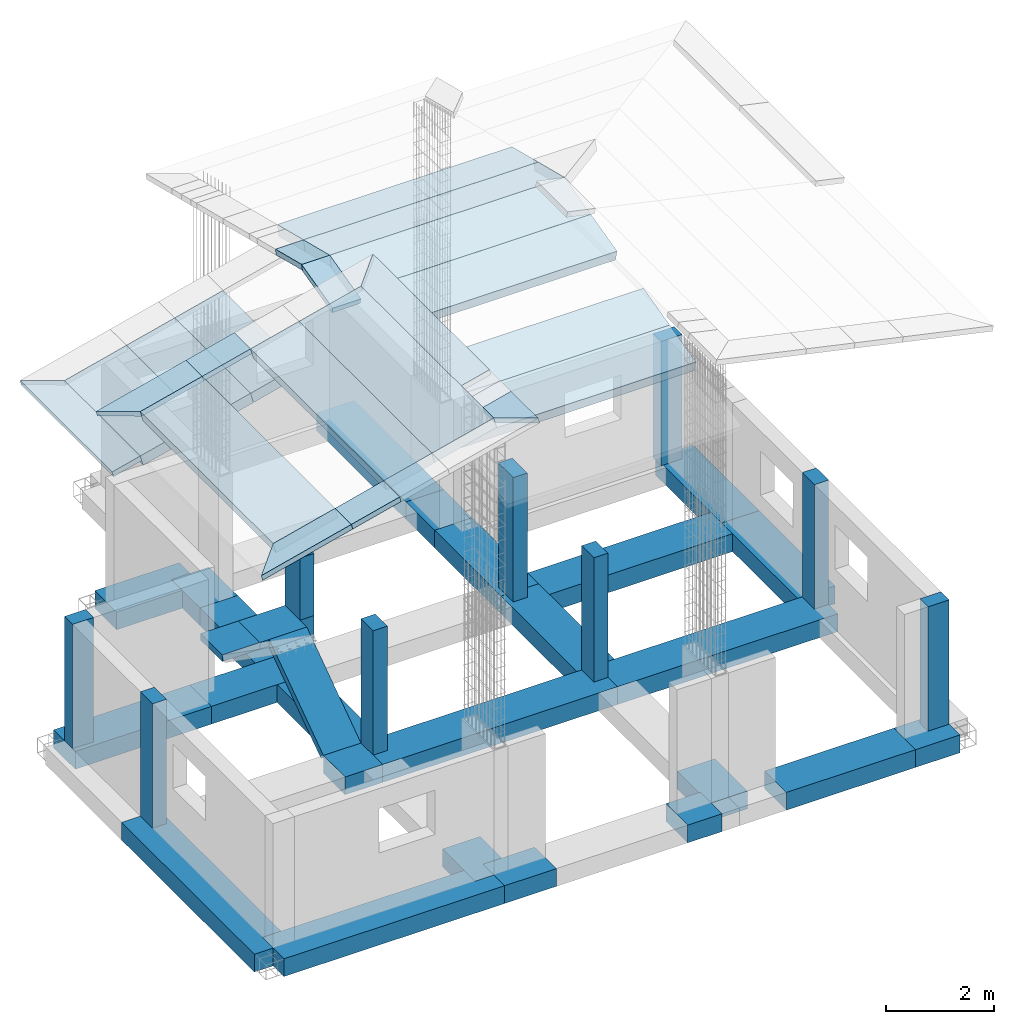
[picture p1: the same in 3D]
Properties of the parts of a building model (IFC4), part 2 of 3

# IfcReinforcingBarType, no part of this type: type
PredefinedType: MAIN; NominalDiameter: 0.02 m; CrossSectionArea: 0.00031416 m2; BarLength: 1.39754 m; Material: Steel

# IfcReinforcingBarType, no part of this type: type
PredefinedType: MAIN; NominalDiameter: 0.016 m; CrossSectionArea: 0.00020106 m2; BarLength: 1.40193 m; Material: Steel

# IfcReinforcingBarType, no part of this type: type
PredefinedType: MAIN; NominalDiameter: 0.02 m; CrossSectionArea: 0.00031416 m2; BarLength: 3.6 m; Material: Steel

# IfcReinforcingBarType, no part of this type: type
PredefinedType: MAIN; NominalDiameter: 0.016 m; CrossSectionArea: 0.00020106 m2; BarLength: 3.6 m; Material: Steel

# IfcReinforcingBarType, no part of this type: type
PredefinedType: MAIN; NominalDiameter: 0.022 m; CrossSectionArea: 0.00038013 m2; BarLength: 4.03 m; Material: Steel

# IfcReinforcingBarType, no part of this type: type
PredefinedType: MAIN; NominalDiameter: 0.016 m; CrossSectionArea: 0.00020106 m2; BarLength: 4.03 m; Material: Steel

# IfcReinforcingBarType, no part of this type: type
PredefinedType: MAIN; NominalDiameter: 0.02 m; CrossSectionArea: 0.00031416 m2; BarLength: 2.34504 m; Material: Steel

# IfcReinforcingBarType, no part of this type: type
PredefinedType: MAIN; NominalDiameter: 0.016 m; CrossSectionArea: 0.00020106 m2; BarLength: 2.34943 m; Material: Steel

# IfcReinforcingBarType, no part of this type: type
PredefinedType: LIGATURE; NominalDiameter: 0.008 m; CrossSectionArea: 0.000050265 m2; BarLength: 1.47881 m; Material: Steel

# IfcReinforcingBarType, no part of this type: type
PredefinedType: MAIN; NominalDiameter: 0.016 m; CrossSectionArea: 0.00020106 m2; BarLength: 1.24193 m; Material: Steel

# IfcReinforcingBarType, no part of this type: type
PredefinedType: MAIN; NominalDiameter: 0.016 m; CrossSectionArea: 0.00020106 m2; BarLength: 3.44 m; Material: Steel

# IfcReinforcingBarType, no part of this type: type
PredefinedType: MAIN; NominalDiameter: 0.016 m; CrossSectionArea: 0.00020106 m2; BarLength: 3.80116 m; Material: Steel

# IfcReinforcingBarType, no part of this type: type
PredefinedType: MAIN; NominalDiameter: 0.016 m; CrossSectionArea: 0.00020106 m2; BarLength: 3.79 m; Material: Steel

# IfcReinforcingBarType, no part of this type: type
PredefinedType: MAIN; NominalDiameter: 0.016 m; CrossSectionArea: 0.00020106 m2; BarLength: 3.79718 m; Material: Steel

# IfcReinforcingBarType, no part of this type: type
PredefinedType: MAIN; NominalDiameter: 0.016 m; CrossSectionArea: 0.00020106 m2; BarLength: 3.79406 m; Material: Steel

# IfcReinforcingBarType, no part of this type: type
PredefinedType: MAIN; NominalDiameter: 0.016 m; CrossSectionArea: 0.00020106 m2; BarLength: 3.79181 m; Material: Steel

# IfcReinforcingBarType, no part of this type: type
PredefinedType: MAIN; NominalDiameter: 0.016 m; CrossSectionArea: 0.00020106 m2; BarLength: 3.79045 m; Material: Steel

# IfcReinforcingBarType, no part of this type: type
PredefinedType: MAIN; NominalDiameter: 0.02 m; CrossSectionArea: 0.00031416 m2; BarLength: 4.11173 m; Material: Steel

# IfcReinforcingBarType, no part of this type: type
PredefinedType: MAIN; NominalDiameter: 0.016 m; CrossSectionArea: 0.00020106 m2; BarLength: 4.11613 m; Material: Steel

# IfcReinforcingBarType, no part of this type: type
PredefinedType: LIGATURE; NominalDiameter: 0.008 m; CrossSectionArea: 0.000050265 m2; BarLength: 1.6788 m; Material: Steel

# IfcReinforcingBarType, no part of this type: type
PredefinedType: LIGATURE; NominalDiameter: 0.008 m; CrossSectionArea: 0.000050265 m2; BarLength: 0.933255 m; Material: Steel

# IfcReinforcingBarType, no part of this type: type
PredefinedType: LIGATURE; NominalDiameter: 0.01 m; CrossSectionArea: 0.00007854 m2; BarLength: 1.68982 m; Material: Steel

# IfcReinforcingBarType, no part of this type: type
PredefinedType: LIGATURE; NominalDiameter: 0.01 m; CrossSectionArea: 0.00007854 m2; BarLength: 0.936286 m; Material: Steel

# IfcReinforcingBarType, no part of this type: type
PredefinedType: LIGATURE; NominalDiameter: 0.008 m; CrossSectionArea: 0.000050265 m2; BarLength: 1.47881 m; Material: Steel

# IfcReinforcingBarType, no part of this type: type
PredefinedType: MAIN; NominalDiameter: 0.022 m; CrossSectionArea: 0.00038013 m2; BarLength: 1.47534 m; Material: Steel

# IfcReinforcingBarType, no part of this type: type
PredefinedType: MAIN; NominalDiameter: 0.016 m; CrossSectionArea: 0.00020106 m2; BarLength: 1.48193 m; Material: Steel

# IfcReinforcingBarType, no part of this type: type
PredefinedType: MAIN; NominalDiameter: 0.022 m; CrossSectionArea: 0.00038013 m2; BarLength: 3.68 m; Material: Steel

# IfcReinforcingBarType, no part of this type: type
PredefinedType: MAIN; NominalDiameter: 0.016 m; CrossSectionArea: 0.00020106 m2; BarLength: 3.68 m; Material: Steel

# IfcReinforcingBarType, no part of this type: type
PredefinedType: MAIN; NominalDiameter: 0.022 m; CrossSectionArea: 0.00038013 m2; BarLength: 4.03282 m; Material: Steel

# IfcReinforcingBarType, no part of this type: type
PredefinedType: MAIN; NominalDiameter: 0.016 m; CrossSectionArea: 0.00020106 m2; BarLength: 4.03 m; Material: Steel

# IfcReinforcingBarType, no part of this type: type
PredefinedType: MAIN; NominalDiameter: 0.02 m; CrossSectionArea: 0.00031416 m2; BarLength: 4.11174 m; Material: Steel

# IfcReinforcingBarType, no part of this type: type
PredefinedType: MAIN; NominalDiameter: 0.016 m; CrossSectionArea: 0.00020106 m2; BarLength: 4.11613 m; Material: Steel

# IfcReinforcingBarType, no part of this type: type
PredefinedType: LIGATURE; NominalDiameter: 0.008 m; CrossSectionArea: 0.000050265 m2; BarLength: 1.6788 m; Material: Steel

# IfcReinforcingBarType, no part of this type: type
PredefinedType: LIGATURE; NominalDiameter: 0.008 m; CrossSectionArea: 0.000050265 m2; BarLength: 0.478429 m; Material: Steel

# IfcReinforcingBarType, no part of this type: type
PredefinedType: LIGATURE; NominalDiameter: 0.008 m; CrossSectionArea: 0.000050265 m2; BarLength: 1.47881 m; Material: Steel

# IfcReinforcingBarType, no part of this type: type
PredefinedType: MAIN; NominalDiameter: 0.02 m; CrossSectionArea: 0.00031416 m2; BarLength: 1.39754 m; Material: Steel

# IfcReinforcingBarType, no part of this type: type
PredefinedType: MAIN; NominalDiameter: 0.016 m; CrossSectionArea: 0.00020106 m2; BarLength: 1.40193 m; Material: Steel

# IfcReinforcingBarType, no part of this type: type
PredefinedType: MAIN; NominalDiameter: 0.02 m; CrossSectionArea: 0.00031416 m2; BarLength: 3.6 m; Material: Steel

# IfcReinforcingBarType, no part of this type: type
PredefinedType: MAIN; NominalDiameter: 0.016 m; CrossSectionArea: 0.00020106 m2; BarLength: 3.6 m; Material: Steel

# IfcReinforcingBarType, no part of this type: type
PredefinedType: MAIN; NominalDiameter: 0.022 m; CrossSectionArea: 0.00038013 m2; BarLength: 4.03 m; Material: Steel

# IfcReinforcingBarType, no part of this type: type
PredefinedType: MAIN; NominalDiameter: 0.016 m; CrossSectionArea: 0.00020106 m2; BarLength: 4.03 m; Material: Steel

# IfcReinforcingBarType, no part of this type: type
PredefinedType: MAIN; NominalDiameter: 0.02 m; CrossSectionArea: 0.00031416 m2; BarLength: 3.49504 m; Material: Steel

# IfcReinforcingBarType, no part of this type: type
PredefinedType: MAIN; NominalDiameter: 0.016 m; CrossSectionArea: 0.00020106 m2; BarLength: 3.49943 m; Material: Steel

# IfcReinforcingBarType, no part of this type: type
PredefinedType: LIGATURE; NominalDiameter: 0.008 m; CrossSectionArea: 0.000050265 m2; BarLength: 1.47881 m; Material: Steel

# IfcReinforcingBarType, no part of this type: type
PredefinedType: MAIN; NominalDiameter: 0.02 m; CrossSectionArea: 0.00031416 m2; BarLength: 1.39754 m; Material: Steel

# IfcReinforcingBarType, no part of this type: type
PredefinedType: MAIN; NominalDiameter: 0.016 m; CrossSectionArea: 0.00020106 m2; BarLength: 1.40193 m; Material: Steel

# IfcReinforcingBarType, no part of this type: type
PredefinedType: MAIN; NominalDiameter: 0.02 m; CrossSectionArea: 0.00031416 m2; BarLength: 3.6 m; Material: Steel

# IfcReinforcingBarType, no part of this type: type
PredefinedType: MAIN; NominalDiameter: 0.016 m; CrossSectionArea: 0.00020106 m2; BarLength: 3.6 m; Material: Steel

# IfcReinforcingBarType, no part of this type: type
PredefinedType: MAIN; NominalDiameter: 0.02 m; CrossSectionArea: 0.00031416 m2; BarLength: 3.95 m; Material: Steel

# IfcReinforcingBarType, no part of this type: type
PredefinedType: MAIN; NominalDiameter: 0.016 m; CrossSectionArea: 0.00020106 m2; BarLength: 3.95 m; Material: Steel

# IfcReinforcingBarType, no part of this type: type
PredefinedType: MAIN; NominalDiameter: 0.02 m; CrossSectionArea: 0.00031416 m2; BarLength: 3.49504 m; Material: Steel

# IfcReinforcingBarType, no part of this type: type
PredefinedType: MAIN; NominalDiameter: 0.016 m; CrossSectionArea: 0.00020106 m2; BarLength: 3.49943 m; Material: Steel

# IfcReinforcingBarType, no part of this type: type
PredefinedType: LIGATURE; NominalDiameter: 0.008 m; CrossSectionArea: 0.000050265 m2; BarLength: 1.47881 m; Material: Steel

# IfcReinforcingBarType, no part of this type: type
PredefinedType: LIGATURE; NominalDiameter: 0.008 m; CrossSectionArea: 0.000050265 m2; BarLength: 1.50681 m; Material: Steel

# IfcReinforcingBarType, no part of this type: type
PredefinedType: MAIN; NominalDiameter: 0.018 m; CrossSectionArea: 0.00025447 m2; BarLength: 3.95455 m; Material: Steel

# IfcReinforcingBarType, no part of this type: type
PredefinedType: MAIN; NominalDiameter: 0.012 m; CrossSectionArea: 0.0001131 m2; BarLength: 3.91455 m; Material: Steel

# IfcReinforcingBarType, no part of this type: type
PredefinedType: LIGATURE; NominalDiameter: 0.008 m; CrossSectionArea: 0.000050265 m2; BarLength: 1.30681 m; Material: Steel

# IfcReinforcingBarType, no part of this type: type
PredefinedType: MAIN; NominalDiameter: 0.016 m; CrossSectionArea: 0.00020106 m2; BarLength: 5.26321 m; Material: Steel

# IfcReinforcingBarType, no part of this type: type
PredefinedType: MAIN; NominalDiameter: 0.014 m; CrossSectionArea: 0.00015394 m2; BarLength: 5.42321 m; Material: Steel

# IfcReinforcingBarType, no part of this type: type
PredefinedType: LIGATURE; NominalDiameter: 0.008 m; CrossSectionArea: 0.000050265 m2; BarLength: 1.50681 m; Material: Steel

# IfcReinforcingBarType, no part of this type: type
PredefinedType: LIGATURE; NominalDiameter: 0.008 m; CrossSectionArea: 0.000050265 m2; BarLength: 1.10682 m; Material: Steel

# IfcReinforcingBarType, no part of this type: type
PredefinedType: MAIN; NominalDiameter: 0.018 m; CrossSectionArea: 0.00025447 m2; BarLength: 5.42122 m; Material: Steel

# IfcReinforcingBarType, no part of this type: type
PredefinedType: MAIN; NominalDiameter: 0.016 m; CrossSectionArea: 0.00020106 m2; BarLength: 10.2064 m; Material: Steel

# IfcReinforcingBarType, no part of this type: type
PredefinedType: MAIN; NominalDiameter: 0.014 m; CrossSectionArea: 0.00015394 m2; BarLength: 11.4956 m; Material: Steel

# IfcReinforcingBarType, no part of this type: type
PredefinedType: MAIN; NominalDiameter: 0.014 m; CrossSectionArea: 0.00015394 m2; BarLength: 2.5 m; Material: Steel

# IfcReinforcingBarType, no part of this type: type
PredefinedType: MAIN; NominalDiameter: 0.018 m; CrossSectionArea: 0.00025447 m2; BarLength: 4.49561 m; Material: Steel

# IfcReinforcingBarType, no part of this type: type
PredefinedType: MAIN; NominalDiameter: 0.012 m; CrossSectionArea: 0.0001131 m2; BarLength: 6.51622 m; Material: Steel

# IfcReinforcingBarType, no part of this type: type
PredefinedType: LIGATURE; NominalDiameter: 0.008 m; CrossSectionArea: 0.000050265 m2; BarLength: 1.50681 m; Material: Steel

# IfcReinforcingBarType, no part of this type: type
PredefinedType: LIGATURE; NominalDiameter: 0.008 m; CrossSectionArea: 0.000050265 m2; BarLength: 1.10682 m; Material: Steel

# IfcReinforcingBarType, no part of this type: type
PredefinedType: MAIN; NominalDiameter: 0.016 m; CrossSectionArea: 0.00020106 m2; BarLength: 10.2064 m; Material: Steel

# IfcReinforcingBarType, no part of this type: type
PredefinedType: MAIN; NominalDiameter: 0.018 m; CrossSectionArea: 0.00025447 m2; BarLength: 2.52121 m; Material: Steel

# IfcReinforcingBarType, no part of this type: type
PredefinedType: MAIN; NominalDiameter: 0.014 m; CrossSectionArea: 0.00015394 m2; BarLength: 10.9956 m; Material: Steel

# IfcReinforcingBarType, no part of this type: type
PredefinedType: MAIN; NominalDiameter: 0.018 m; CrossSectionArea: 0.00025447 m2; BarLength: 2.49561 m; Material: Steel

# IfcReinforcingBarType, no part of this type: type
PredefinedType: MAIN; NominalDiameter: 0.012 m; CrossSectionArea: 0.0001131 m2; BarLength: 3.61621 m; Material: Steel

# IfcReinforcingBarType, no part of this type: type
PredefinedType: MAIN; NominalDiameter: 0.014 m; CrossSectionArea: 0.00015394 m2; BarLength: 2 m; Material: Steel

# IfcReinforcingBarType, no part of this type: type
PredefinedType: LIGATURE; NominalDiameter: 0.008 m; CrossSectionArea: 0.000050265 m2; BarLength: 1.10682 m; Material: Steel

# IfcReinforcingBarType, no part of this type: type
PredefinedType: MAIN; NominalDiameter: 0.016 m; CrossSectionArea: 0.00020106 m2; BarLength: 5.26121 m; Material: Steel

# IfcReinforcingBarType, no part of this type: type
PredefinedType: MAIN; NominalDiameter: 0.014 m; CrossSectionArea: 0.00015394 m2; BarLength: 5.26121 m; Material: Steel

# IfcReinforcingBarType, no part of this type: type
PredefinedType: LIGATURE; NominalDiameter: 0.008 m; CrossSectionArea: 0.000050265 m2; BarLength: 1.10682 m; Material: Steel

# IfcReinforcingBarType, no part of this type: type
PredefinedType: MAIN; NominalDiameter: 0.016 m; CrossSectionArea: 0.00020106 m2; BarLength: 3.36321 m; Material: Steel

# IfcReinforcingBarType, no part of this type: type
PredefinedType: MAIN; NominalDiameter: 0.014 m; CrossSectionArea: 0.00015394 m2; BarLength: 3.52321 m; Material: Steel

# IfcReinforcingBarType, no part of this type: type
PredefinedType: LIGATURE; NominalDiameter: 0.008 m; CrossSectionArea: 0.000050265 m2; BarLength: 1.50681 m; Material: Steel

# IfcReinforcingBarType, no part of this type: type
PredefinedType: MAIN; NominalDiameter: 0.018 m; CrossSectionArea: 0.00025447 m2; BarLength: 10.1212 m; Material: Steel

# IfcReinforcingBarType, no part of this type: type
PredefinedType: MAIN; NominalDiameter: 0.018 m; CrossSectionArea: 0.00025447 m2; BarLength: 10.0422 m; Material: Steel

# IfcReinforcingBarType, no part of this type: type
PredefinedType: MAIN; NominalDiameter: 0.012 m; CrossSectionArea: 0.0001131 m2; BarLength: 5.07971 m; Material: Steel

# IfcReinforcingBarType, no part of this type: type
PredefinedType: MAIN; NominalDiameter: 0.012 m; CrossSectionArea: 0.0001131 m2; BarLength: 5.12622 m; Material: Steel

# IfcReinforcingBarType, no part of this type: type
PredefinedType: MAIN; NominalDiameter: 0.012 m; CrossSectionArea: 0.0001131 m2; BarLength: 4.32871 m; Material: Steel

# IfcReinforcingBarType, no part of this type: type
PredefinedType: LIGATURE; NominalDiameter: 0.008 m; CrossSectionArea: 0.000050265 m2; BarLength: 1.50681 m; Material: Steel

# IfcReinforcingBarType, no part of this type: type
PredefinedType: MAIN; NominalDiameter: 0.018 m; CrossSectionArea: 0.00025447 m2; BarLength: 9.77122 m; Material: Steel

# IfcReinforcingBarType, no part of this type: type
PredefinedType: MAIN; NominalDiameter: 0.014 m; CrossSectionArea: 0.00015394 m2; BarLength: 9.77122 m; Material: Steel

# IfcReinforcingBarType, no part of this type: type
PredefinedType: MAIN; NominalDiameter: 0.018 m; CrossSectionArea: 0.00025447 m2; BarLength: 10.0422 m; Material: Steel

# IfcReinforcingBarType, no part of this type: type
PredefinedType: MAIN; NominalDiameter: 0.012 m; CrossSectionArea: 0.0001131 m2; BarLength: 5.14846 m; Material: Steel

# IfcReinforcingBarType, no part of this type: type
PredefinedType: MAIN; NominalDiameter: 0.012 m; CrossSectionArea: 0.0001131 m2; BarLength: 5.33246 m; Material: Steel

# IfcReinforcingBarType, no part of this type: type
PredefinedType: MAIN; NominalDiameter: 0.012 m; CrossSectionArea: 0.0001131 m2; BarLength: 3.77246 m; Material: Steel

# IfcReinforcingBarType, no part of this type: type
PredefinedType: LIGATURE; NominalDiameter: 0.008 m; CrossSectionArea: 0.000050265 m2; BarLength: 1.50681 m; Material: Steel

# IfcReinforcingBarType, no part of this type: type
PredefinedType: MAIN; NominalDiameter: 0.018 m; CrossSectionArea: 0.00025447 m2; BarLength: 4.14622 m; Material: Steel

# IfcReinforcingBarType, no part of this type: type
PredefinedType: MAIN; NominalDiameter: 0.012 m; CrossSectionArea: 0.0001131 m2; BarLength: 4.10622 m; Material: Steel

# IfcReinforcingBarType, no part of this type: type
PredefinedType: LIGATURE; NominalDiameter: 0.008 m; CrossSectionArea: 0.000050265 m2; BarLength: 1.50681 m; Material: Steel

# IfcReinforcingBarType, no part of this type: type
PredefinedType: MAIN; NominalDiameter: 0.018 m; CrossSectionArea: 0.00025447 m2; BarLength: 5.42221 m; Material: Steel

# IfcReinforcingBarType, no part of this type: type
PredefinedType: MAIN; NominalDiameter: 0.012 m; CrossSectionArea: 0.0001131 m2; BarLength: 5.38221 m; Material: Steel

# IfcReinforcingBarType, no part of this type: type
PredefinedType: LIGATURE; NominalDiameter: 0.008 m; CrossSectionArea: 0.000050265 m2; BarLength: 1.50681 m; Material: Steel

# IfcReinforcingBarType, no part of this type: type
PredefinedType: MAIN; NominalDiameter: 0.018 m; CrossSectionArea: 0.00025447 m2; BarLength: 5.42321 m; Material: Steel

# IfcReinforcingBarType, no part of this type: type
PredefinedType: MAIN; NominalDiameter: 0.014 m; CrossSectionArea: 0.00015394 m2; BarLength: 5.42321 m; Material: Steel

# IfcReinforcingBarType, no part of this type: type
PredefinedType: MAIN; NominalDiameter: 0.012 m; CrossSectionArea: 0.0001131 m2; BarLength: 5.38321 m; Material: Steel

# IfcReinforcingBarType, no part of this type: type
PredefinedType: LIGATURE; NominalDiameter: 0.008 m; CrossSectionArea: 0.000050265 m2; BarLength: 1.5068 m; Material: Steel

# IfcReinforcingBarType, no part of this type: type
PredefinedType: LIGATURE; NominalDiameter: 0.008 m; CrossSectionArea: 0.000050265 m2; BarLength: 1.10682 m; Material: Steel

# IfcReinforcingBarType, no part of this type: type
PredefinedType: MAIN; NominalDiameter: 0.018 m; CrossSectionArea: 0.00025447 m2; BarLength: 5.42221 m; Material: Steel

# IfcReinforcingBarType, no part of this type: type
PredefinedType: MAIN; NominalDiameter: 0.014 m; CrossSectionArea: 0.00015394 m2; BarLength: 5.42221 m; Material: Steel

# IfcReinforcingBarType, no part of this type: type
PredefinedType: MAIN; NominalDiameter: 0.016 m; CrossSectionArea: 0.00020106 m2; BarLength: 10.2074 m; Material: Steel

# IfcReinforcingBarType, no part of this type: type
PredefinedType: MAIN; NominalDiameter: 0.014 m; CrossSectionArea: 0.00015394 m2; BarLength: 11.9956 m; Material: Steel

# IfcReinforcingBarType, no part of this type: type
PredefinedType: MAIN; NominalDiameter: 0.018 m; CrossSectionArea: 0.00025447 m2; BarLength: 4.49561 m; Material: Steel

# IfcReinforcingBarType, no part of this type: type
PredefinedType: MAIN; NominalDiameter: 0.014 m; CrossSectionArea: 0.00015394 m2; BarLength: 2.5 m; Material: Steel

# IfcReinforcingBarType, no part of this type: type
PredefinedType: MAIN; NominalDiameter: 0.012 m; CrossSectionArea: 0.0001131 m2; BarLength: 6.51721 m; Material: Steel

# IfcReinforcingBarType, no part of this type: type
PredefinedType: LIGATURE; NominalDiameter: 0.008 m; CrossSectionArea: 0.000050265 m2; BarLength: 1.50681 m; Material: Steel

# IfcReinforcingBarType, no part of this type: type
PredefinedType: LIGATURE; NominalDiameter: 0.008 m; CrossSectionArea: 0.000050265 m2; BarLength: 1.10682 m; Material: Steel

# IfcReinforcingBarType, no part of this type: type
PredefinedType: MAIN; NominalDiameter: 0.016 m; CrossSectionArea: 0.00020106 m2; BarLength: 10.2074 m; Material: Steel

# IfcReinforcingBarType, no part of this type: type
PredefinedType: MAIN; NominalDiameter: 0.018 m; CrossSectionArea: 0.00025447 m2; BarLength: 5.42221 m; Material: Steel

# IfcReinforcingBarType, no part of this type: type
PredefinedType: MAIN; NominalDiameter: 0.014 m; CrossSectionArea: 0.00015394 m2; BarLength: 11.4956 m; Material: Steel

# IfcReinforcingBarType, no part of this type: type
PredefinedType: MAIN; NominalDiameter: 0.018 m; CrossSectionArea: 0.00025447 m2; BarLength: 4.49561 m; Material: Steel

# IfcReinforcingBarType, no part of this type: type
PredefinedType: MAIN; NominalDiameter: 0.014 m; CrossSectionArea: 0.00015394 m2; BarLength: 2.5 m; Material: Steel

# IfcReinforcingBarType, no part of this type: type
PredefinedType: MAIN; NominalDiameter: 0.012 m; CrossSectionArea: 0.0001131 m2; BarLength: 6.51721 m; Material: Steel

# IfcReinforcingBarType, no part of this type: type
PredefinedType: LIGATURE; NominalDiameter: 0.008 m; CrossSectionArea: 0.000050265 m2; BarLength: 1.50681 m; Material: Steel

# IfcReinforcingBarType, no part of this type: type
PredefinedType: MAIN; NominalDiameter: 0.018 m; CrossSectionArea: 0.00025447 m2; BarLength: 5.42321 m; Material: Steel

# IfcReinforcingBarType, no part of this type: type
PredefinedType: MAIN; NominalDiameter: 0.012 m; CrossSectionArea: 0.0001131 m2; BarLength: 5.38321 m; Material: Steel

# IfcReinforcingBarType, no part of this type: type
PredefinedType: LIGATURE; NominalDiameter: 0.008 m; CrossSectionArea: 0.000050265 m2; BarLength: 1.50681 m; Material: Steel

# IfcReinforcingBarType, no part of this type: type
PredefinedType: MAIN; NominalDiameter: 0.018 m; CrossSectionArea: 0.00025447 m2; BarLength: 5.42121 m; Material: Steel

# IfcReinforcingBarType, no part of this type: type
PredefinedType: MAIN; NominalDiameter: 0.012 m; CrossSectionArea: 0.0001131 m2; BarLength: 5.38121 m; Material: Steel

# IfcReinforcingBarType, no part of this type: type
PredefinedType: LIGATURE; NominalDiameter: 0.008 m; CrossSectionArea: 0.000050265 m2; BarLength: 1.50681 m; Material: Steel

# IfcReinforcingBarType, no part of this type: type
PredefinedType: MAIN; NominalDiameter: 0.018 m; CrossSectionArea: 0.00025447 m2; BarLength: 8.12321 m; Material: Steel

# IfcReinforcingBarType, no part of this type: type
PredefinedType: MAIN; NominalDiameter: 0.012 m; CrossSectionArea: 0.0001131 m2; BarLength: 5.94221 m; Material: Steel

# IfcReinforcingBarType, no part of this type: type
PredefinedType: MAIN; NominalDiameter: 0.012 m; CrossSectionArea: 0.0001131 m2; BarLength: 4.70471 m; Material: Steel

# IfcReinforcingBarType, no part of this type: type
PredefinedType: LIGATURE; NominalDiameter: 0.008 m; CrossSectionArea: 0.000050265 m2; BarLength: 1.10682 m; Material: Steel

# IfcReinforcingBarType, no part of this type: type
PredefinedType: MAIN; NominalDiameter: 0.016 m; CrossSectionArea: 0.00020106 m2; BarLength: 3.36321 m; Material: Steel

# IfcReinforcingBarType, no part of this type: type
PredefinedType: MAIN; NominalDiameter: 0.014 m; CrossSectionArea: 0.00015394 m2; BarLength: 3.52321 m; Material: Steel

# IfcReinforcingBarType, no part of this type: type
PredefinedType: LIGATURE; NominalDiameter: 0.008 m; CrossSectionArea: 0.000050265 m2; BarLength: 1.5068 m; Material: Steel

# IfcReinforcingBarType, no part of this type: type
PredefinedType: MAIN; NominalDiameter: 0.018 m; CrossSectionArea: 0.00025447 m2; BarLength: 10.1212 m; Material: Steel

# IfcReinforcingBarType, no part of this type: type
PredefinedType: MAIN; NominalDiameter: 0.012 m; CrossSectionArea: 0.0001131 m2; BarLength: 5.10371 m; Material: Steel

# IfcReinforcingBarType, no part of this type: type
PredefinedType: MAIN; NominalDiameter: 0.012 m; CrossSectionArea: 0.0001131 m2; BarLength: 5.12622 m; Material: Steel

# IfcReinforcingBarType, no part of this type: type
PredefinedType: MAIN; NominalDiameter: 0.012 m; CrossSectionArea: 0.0001131 m2; BarLength: 4.25371 m; Material: Steel

# IfcReinforcingBarType, no part of this type: type
PredefinedType: LIGATURE; NominalDiameter: 0.008 m; CrossSectionArea: 0.000050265 m2; BarLength: 1.50681 m; Material: Steel

# IfcReinforcingBarType, no part of this type: type
PredefinedType: MAIN; NominalDiameter: 0.018 m; CrossSectionArea: 0.00025447 m2; BarLength: 10.1212 m; Material: Steel

# IfcReinforcingBarType, no part of this type: type
PredefinedType: MAIN; NominalDiameter: 0.014 m; CrossSectionArea: 0.00015394 m2; BarLength: 10.1212 m; Material: Steel

# IfcReinforcingBarType, no part of this type: type
PredefinedType: MAIN; NominalDiameter: 0.012 m; CrossSectionArea: 0.0001131 m2; BarLength: 5.15996 m; Material: Steel

# IfcReinforcingBarType, no part of this type: type
PredefinedType: MAIN; NominalDiameter: 0.012 m; CrossSectionArea: 0.0001131 m2; BarLength: 5.29496 m; Material: Steel

# IfcReinforcingBarType, no part of this type: type
PredefinedType: MAIN; NominalDiameter: 0.012 m; CrossSectionArea: 0.0001131 m2; BarLength: 4.08496 m; Material: Steel

# IfcReinforcingBarType, no part of this type: type
PredefinedType: LIGATURE; NominalDiameter: 0.008 m; CrossSectionArea: 0.000050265 m2; BarLength: 1.50681 m; Material: Steel

# IfcReinforcingBarType, no part of this type: type
PredefinedType: MAIN; NominalDiameter: 0.018 m; CrossSectionArea: 0.00025447 m2; BarLength: 10.5732 m; Material: Steel

# IfcReinforcingBarType, no part of this type: type
PredefinedType: MAIN; NominalDiameter: 0.012 m; CrossSectionArea: 0.0001131 m2; BarLength: 5.96096 m; Material: Steel

# IfcReinforcingBarType, no part of this type: type
PredefinedType: MAIN; NominalDiameter: 0.012 m; CrossSectionArea: 0.0001131 m2; BarLength: 5.44496 m; Material: Steel

# IfcReinforcingBarType, no part of this type: type
PredefinedType: MAIN; NominalDiameter: 0.012 m; CrossSectionArea: 0.0001131 m2; BarLength: 3.73596 m; Material: Steel

# IfcReinforcingBarType, no part of this type: type
PredefinedType: LIGATURE; NominalDiameter: 0.008 m; CrossSectionArea: 0.000050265 m2; BarLength: 1.50681 m; Material: Steel

# IfcReinforcingBarType, no part of this type: type
PredefinedType: MAIN; NominalDiameter: 0.018 m; CrossSectionArea: 0.00025447 m2; BarLength: 5.42221 m; Material: Steel

# IfcReinforcingBarType, no part of this type: type
PredefinedType: MAIN; NominalDiameter: 0.012 m; CrossSectionArea: 0.0001131 m2; BarLength: 5.38221 m; Material: Steel

# IfcReinforcingBarType, no part of this type: type
PredefinedType: LIGATURE; NominalDiameter: 0.008 m; CrossSectionArea: 0.000050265 m2; BarLength: 1.32681 m; Material: Steel

# IfcReinforcingBarType, no part of this type: type
PredefinedType: MAIN; NominalDiameter: 0.018 m; CrossSectionArea: 0.00025447 m2; BarLength: 5.57513 m; Material: Steel

# IfcReinforcingBarType, no part of this type: type
PredefinedType: MAIN; NominalDiameter: 0.016 m; CrossSectionArea: 0.00020106 m2; BarLength: 5.57513 m; Material: Steel

# IfcReinforcingBarType, no part of this type: type
PredefinedType: LIGATURE; NominalDiameter: 0.008 m; CrossSectionArea: 0.000050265 m2; BarLength: 1.32681 m; Material: Steel

# IfcReinforcingBarType, no part of this type: type
PredefinedType: MAIN; NominalDiameter: 0.016 m; CrossSectionArea: 0.00020106 m2; BarLength: 5.42122 m; Material: Steel

# IfcReinforcingBarType, no part of this type: type
PredefinedType: MAIN; NominalDiameter: 0.016 m; CrossSectionArea: 0.00020106 m2; BarLength: 5.42321 m; Material: Steel

# IfcReinforcingBarType, no part of this type: type
PredefinedType: LIGATURE; NominalDiameter: 0.008 m; CrossSectionArea: 0.000050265 m2; BarLength: 1.32681 m; Material: Steel

# IfcReinforcingBarType, no part of this type: type
PredefinedType: MAIN; NominalDiameter: 0.016 m; CrossSectionArea: 0.00020106 m2; BarLength: 5.57513 m; Material: Steel

# IfcReinforcingBarType, no part of this type: type
PredefinedType: MAIN; NominalDiameter: 0.016 m; CrossSectionArea: 0.00020106 m2; BarLength: 5.57513 m; Material: Steel

# IfcReinforcingBarType, no part of this type: type
PredefinedType: LIGATURE; NominalDiameter: 0.008 m; CrossSectionArea: 0.000050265 m2; BarLength: 1.32681 m; Material: Steel

# IfcReinforcingBarType, no part of this type: type
PredefinedType: MAIN; NominalDiameter: 0.016 m; CrossSectionArea: 0.00020106 m2; BarLength: 5.57513 m; Material: Steel

# IfcReinforcingBarType, no part of this type: type
PredefinedType: MAIN; NominalDiameter: 0.016 m; CrossSectionArea: 0.00020106 m2; BarLength: 5.57513 m; Material: Steel

# IfcReinforcingBarType, no part of this type: type
PredefinedType: LIGATURE; NominalDiameter: 0.008 m; CrossSectionArea: 0.000050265 m2; BarLength: 1.32681 m; Material: Steel

# IfcReinforcingBarType, no part of this type: type
PredefinedType: MAIN; NominalDiameter: 0.016 m; CrossSectionArea: 0.00020106 m2; BarLength: 5.42222 m; Material: Steel

# IfcReinforcingBarType, no part of this type: type
PredefinedType: MAIN; NominalDiameter: 0.016 m; CrossSectionArea: 0.00020106 m2; BarLength: 5.42322 m; Material: Steel

# IfcReinforcingBarType, no part of this type: type
PredefinedType: LIGATURE; NominalDiameter: 0.008 m; CrossSectionArea: 0.000050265 m2; BarLength: 1.32681 m; Material: Steel

# IfcReinforcingBarType, no part of this type: type
PredefinedType: MAIN; NominalDiameter: 0.016 m; CrossSectionArea: 0.00020106 m2; BarLength: 5.42122 m; Material: Steel

# IfcReinforcingBarType, no part of this type: type
PredefinedType: LIGATURE; NominalDiameter: 0.008 m; CrossSectionArea: 0.000050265 m2; BarLength: 1.32681 m; Material: Steel

# IfcReinforcingBarType, no part of this type: type
PredefinedType: MAIN; NominalDiameter: 0.016 m; CrossSectionArea: 0.00020106 m2; BarLength: 5.32121 m; Material: Steel

# IfcReinforcingBarType, no part of this type: type
PredefinedType: MAIN; NominalDiameter: 0.016 m; CrossSectionArea: 0.00020106 m2; BarLength: 5.32321 m; Material: Steel

# IfcReinforcingBarType, no part of this type: type
PredefinedType: LIGATURE; NominalDiameter: 0.008 m; CrossSectionArea: 0.000050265 m2; BarLength: 1.32681 m; Material: Steel

# IfcReinforcingBarType, no part of this type: type
PredefinedType: MAIN; NominalDiameter: 0.016 m; CrossSectionArea: 0.00020106 m2; BarLength: 4.52121 m; Material: Steel

# IfcReinforcingBarType, no part of this type: type
PredefinedType: MAIN; NominalDiameter: 0.016 m; CrossSectionArea: 0.00020106 m2; BarLength: 4.52221 m; Material: Steel

# IfcReinforcingBarType, no part of this type: type
PredefinedType: LIGATURE; NominalDiameter: 0.008 m; CrossSectionArea: 0.000050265 m2; BarLength: 1.32681 m; Material: Steel

# IfcReinforcingBarType, no part of this type: type
PredefinedType: MAIN; NominalDiameter: 0.016 m; CrossSectionArea: 0.00020106 m2; BarLength: 5.67121 m; Material: Steel

# IfcReinforcingBarType, no part of this type: type
PredefinedType: LIGATURE; NominalDiameter: 0.008 m; CrossSectionArea: 0.000050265 m2; BarLength: 1.32681 m; Material: Steel

# IfcReinforcingBarType, no part of this type: type
PredefinedType: MAIN; NominalDiameter: 0.016 m; CrossSectionArea: 0.00020106 m2; BarLength: 10.5722 m; Material: Steel

# IfcReinforcingBarType, no part of this type: type
PredefinedType: MAIN; NominalDiameter: 0.016 m; CrossSectionArea: 0.00020106 m2; BarLength: 10.5732 m; Material: Steel

# IfcReinforcingBarType, no part of this type: type
PredefinedType: LIGATURE; NominalDiameter: 0.008 m; CrossSectionArea: 0.000050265 m2; BarLength: 1.32681 m; Material: Steel

# IfcReinforcingBarType, no part of this type: type
PredefinedType: MAIN; NominalDiameter: 0.016 m; CrossSectionArea: 0.00020106 m2; BarLength: 6.97247 m; Material: Steel

# IfcReinforcingBarType, no part of this type: type
PredefinedType: MAIN; NominalDiameter: 0.016 m; CrossSectionArea: 0.00020106 m2; BarLength: 6.74213 m; Material: Steel

# IfcReinforcingBarType, no part of this type: type
PredefinedType: LIGATURE; NominalDiameter: 0.008 m; CrossSectionArea: 0.000050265 m2; BarLength: 1.32681 m; Material: Steel

# IfcReinforcingBarType, no part of this type: type
PredefinedType: MAIN; NominalDiameter: 0.018 m; CrossSectionArea: 0.00025447 m2; BarLength: 5.53911 m; Material: Steel

# IfcReinforcingBarType, no part of this type: type
PredefinedType: MAIN; NominalDiameter: 0.016 m; CrossSectionArea: 0.00020106 m2; BarLength: 5.53891 m; Material: Steel

# IfcReinforcingBarType, no part of this type: type
PredefinedType: LIGATURE; NominalDiameter: 0.008 m; CrossSectionArea: 0.000050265 m2; BarLength: 1.32681 m; Material: Steel

# IfcReinforcingBarType, no part of this type: type
PredefinedType: MAIN; NominalDiameter: 0.016 m; CrossSectionArea: 0.00020106 m2; BarLength: 5.57513 m; Material: Steel

# IfcReinforcingBarType, no part of this type: type
PredefinedType: MAIN; NominalDiameter: 0.016 m; CrossSectionArea: 0.00020106 m2; BarLength: 5.57513 m; Material: Steel

# IfcReinforcingBarType, no part of this type: type
PredefinedType: LIGATURE; NominalDiameter: 0.008 m; CrossSectionArea: 0.000050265 m2; BarLength: 1.32681 m; Material: Steel

# IfcReinforcingBarType, no part of this type: type
PredefinedType: MAIN; NominalDiameter: 0.016 m; CrossSectionArea: 0.00020106 m2; BarLength: 3.67122 m; Material: Steel

# IfcReinforcingBarType, no part of this type: type
PredefinedType: MAIN; NominalDiameter: 0.016 m; CrossSectionArea: 0.00020106 m2; BarLength: 3.67221 m; Material: Steel

# IfcReinforcingBarType, no part of this type: type
PredefinedType: LIGATURE; NominalDiameter: 0.008 m; CrossSectionArea: 0.000050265 m2; BarLength: 1.32681 m; Material: Steel

# IfcReinforcingBarType, no part of this type: type
PredefinedType: MAIN; NominalDiameter: 0.018 m; CrossSectionArea: 0.00025447 m2; BarLength: 5 m; Material: Steel

# IfcReinforcingBarType, no part of this type: type
PredefinedType: MAIN; NominalDiameter: 0.016 m; CrossSectionArea: 0.00020106 m2; BarLength: 5 m; Material: Steel

# IfcReinforcingBarType, no part of this type: type
PredefinedType: MAIN; NominalDiameter: 0.018 m; CrossSectionArea: 0.00025447 m2; BarLength: 2.99238 m; Material: Steel

# IfcReinforcingBarType, no part of this type: type
PredefinedType: MAIN; NominalDiameter: 0.014 m; CrossSectionArea: 0.00015394 m2; BarLength: 2.99238 m; Material: Steel

# IfcReinforcingBarType, no part of this type: type
PredefinedType: MAIN; NominalDiameter: 0.016 m; CrossSectionArea: 0.00020106 m2; BarLength: 10.4194 m; Material: Steel

# IfcReinforcingBarType, no part of this type: type
PredefinedType: MAIN; NominalDiameter: 0.016 m; CrossSectionArea: 0.00020106 m2; BarLength: 4.49985 m; Material: Steel

# IfcReinforcingBarType, no part of this type: type
PredefinedType: MAIN; NominalDiameter: 0.014 m; CrossSectionArea: 0.00015394 m2; BarLength: 4.49985 m; Material: Steel

# IfcReinforcingBarType, no part of this type: type
PredefinedType: MAIN; NominalDiameter: 0.016 m; CrossSectionArea: 0.00020106 m2; BarLength: 2.29763 m; Material: Steel

# IfcReinforcingBarType, no part of this type: type
PredefinedType: MAIN; NominalDiameter: 0.014 m; CrossSectionArea: 0.00015394 m2; BarLength: 2.29763 m; Material: Steel

# IfcReinforcingBarType, no part of this type: type
PredefinedType: MAIN; NominalDiameter: 0.016 m; CrossSectionArea: 0.00020106 m2; BarLength: 1.99985 m; Material: Steel

# IfcReinforcingBarType, no part of this type: type
PredefinedType: MAIN; NominalDiameter: 0.014 m; CrossSectionArea: 0.00015394 m2; BarLength: 1.99985 m; Material: Steel

# IfcReinforcingBarType, no part of this type: type
PredefinedType: LIGATURE; NominalDiameter: 0.008 m; CrossSectionArea: 0.000050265 m2; BarLength: 1.32681 m; Material: Steel

# IfcReinforcingBarType, no part of this type: type
PredefinedType: MAIN; NominalDiameter: 0.016 m; CrossSectionArea: 0.00020106 m2; BarLength: 4.99238 m; Material: Steel

# IfcReinforcingBarType, no part of this type: type
PredefinedType: MAIN; NominalDiameter: 0.016 m; CrossSectionArea: 0.00020106 m2; BarLength: 6.99223 m; Material: Steel

# IfcReinforcingBarType, no part of this type: type
PredefinedType: MAIN; NominalDiameter: 0.018 m; CrossSectionArea: 0.00025447 m2; BarLength: 3.5 m; Material: Steel

# IfcReinforcingBarType, no part of this type: type
PredefinedType: MAIN; NominalDiameter: 0.014 m; CrossSectionArea: 0.00015394 m2; BarLength: 3.5 m; Material: Steel

# IfcReinforcingBarType, no part of this type: type
PredefinedType: MAIN; NominalDiameter: 0.016 m; CrossSectionArea: 0.00020106 m2; BarLength: 10.4246 m; Material: Steel

# IfcReinforcingBarType, no part of this type: type
PredefinedType: LIGATURE; NominalDiameter: 0.008 m; CrossSectionArea: 0.000050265 m2; BarLength: 1.32681 m; Material: Steel

# IfcReinforcingBarType, no part of this type: type
PredefinedType: MAIN; NominalDiameter: 0.018 m; CrossSectionArea: 0.00025447 m2; BarLength: 5.51848 m; Material: Steel

# IfcReinforcingBarType, no part of this type: type
PredefinedType: MAIN; NominalDiameter: 0.016 m; CrossSectionArea: 0.00020106 m2; BarLength: 5.53891 m; Material: Steel

# IfcReinforcingBarType, no part of this type: type
PredefinedType: LIGATURE; NominalDiameter: 0.008 m; CrossSectionArea: 0.000050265 m2; BarLength: 1.32681 m; Material: Steel

# IfcReinforcingBarType, no part of this type: type
PredefinedType: MAIN; NominalDiameter: 0.016 m; CrossSectionArea: 0.00020106 m2; BarLength: 3.67121 m; Material: Steel

# IfcReinforcingBarType, no part of this type: type
PredefinedType: MAIN; NominalDiameter: 0.016 m; CrossSectionArea: 0.00020106 m2; BarLength: 3.67221 m; Material: Steel

# IfcReinforcingBarType, no part of this type: type
PredefinedType: LIGATURE; NominalDiameter: 0.008 m; CrossSectionArea: 0.000050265 m2; BarLength: 2.42679 m; Material: Steel

# IfcReinforcingBarType, no part of this type: type
PredefinedType: MAIN; NominalDiameter: 0.016 m; CrossSectionArea: 0.00020106 m2; BarLength: 11.8364 m; Material: Steel

# IfcReinforcingBarType, no part of this type: type
PredefinedType: MAIN; NominalDiameter: 0.016 m; CrossSectionArea: 0.00020106 m2; BarLength: 4.83642 m; Material: Steel

# IfcReinforcingBarType, no part of this type: type
PredefinedType: MAIN; NominalDiameter: 0.016 m; CrossSectionArea: 0.00020106 m2; BarLength: 2 m; Material: Steel

# IfcReinforcingBarType, no part of this type: type
PredefinedType: MAIN; NominalDiameter: 0.016 m; CrossSectionArea: 0.00020106 m2; BarLength: 1.5 m; Material: Steel

# IfcReinforcingBarType, no part of this type: type
PredefinedType: MAIN; NominalDiameter: 0.016 m; CrossSectionArea: 0.00020106 m2; BarLength: 3.85163 m; Material: Steel

# IfcReinforcingBarType, no part of this type: type
PredefinedType: MAIN; NominalDiameter: 0.016 m; CrossSectionArea: 0.00020106 m2; BarLength: 3.80163 m; Material: Steel

# IfcReinforcingBarType, no part of this type: type
PredefinedType: LIGATURE; NominalDiameter: 0.008 m; CrossSectionArea: 0.000050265 m2; BarLength: 2.42679 m; Material: Steel

# IfcReinforcingBarType, no part of this type: type
PredefinedType: MAIN; NominalDiameter: 0.016 m; CrossSectionArea: 0.00020106 m2; BarLength: 10.8364 m; Material: Steel

# IfcReinforcingBarType, no part of this type: type
PredefinedType: MAIN; NominalDiameter: 0.016 m; CrossSectionArea: 0.00020106 m2; BarLength: 2.5 m; Material: Steel

# IfcReinforcingBarType, no part of this type: type
PredefinedType: MAIN; NominalDiameter: 0.016 m; CrossSectionArea: 0.00020106 m2; BarLength: 5.83642 m; Material: Steel

# IfcReinforcingBarType, no part of this type: type
PredefinedType: MAIN; NominalDiameter: 0.016 m; CrossSectionArea: 0.00020106 m2; BarLength: 9.49561 m; Material: Steel

# IfcReinforcingBarType, no part of this type: type
PredefinedType: MAIN; NominalDiameter: 0.016 m; CrossSectionArea: 0.00020106 m2; BarLength: 7.49561 m; Material: Steel

# IfcReinforcingBarType, no part of this type: type
PredefinedType: MAIN; NominalDiameter: 0.016 m; CrossSectionArea: 0.00020106 m2; BarLength: 2 m; Material: Steel

# IfcReinforcingBarType, no part of this type: type
PredefinedType: LIGATURE; NominalDiameter: 0.008 m; CrossSectionArea: 0.000050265 m2; BarLength: 2.42679 m; Material: Steel

# IfcReinforcingBarType, no part of this type: type
PredefinedType: MAIN; NominalDiameter: 0.016 m; CrossSectionArea: 0.00020106 m2; BarLength: 10.8364 m; Material: Steel

# IfcReinforcingBarType, no part of this type: type
PredefinedType: MAIN; NominalDiameter: 0.016 m; CrossSectionArea: 0.00020106 m2; BarLength: 5.83642 m; Material: Steel

# IfcReinforcingBarType, no part of this type: type
PredefinedType: MAIN; NominalDiameter: 0.016 m; CrossSectionArea: 0.00020106 m2; BarLength: 9.49561 m; Material: Steel

# IfcReinforcingBarType, no part of this type: type
PredefinedType: MAIN; NominalDiameter: 0.016 m; CrossSectionArea: 0.00020106 m2; BarLength: 7.49561 m; Material: Steel

# IfcReinforcingBarType, no part of this type: type
PredefinedType: MAIN; NominalDiameter: 0.016 m; CrossSectionArea: 0.00020106 m2; BarLength: 2 m; Material: Steel

# IfcReinforcingBarType, no part of this type: type
PredefinedType: LIGATURE; NominalDiameter: 0.008 m; CrossSectionArea: 0.000050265 m2; BarLength: 2.42679 m; Material: Steel

# IfcReinforcingBarType, no part of this type: type
PredefinedType: MAIN; NominalDiameter: 0.016 m; CrossSectionArea: 0.00020106 m2; BarLength: 5.92121 m; Material: Steel

# IfcReinforcingBarType, no part of this type: type
PredefinedType: LIGATURE; NominalDiameter: 0.008 m; CrossSectionArea: 0.000050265 m2; BarLength: 2.42679 m; Material: Steel

# IfcReinforcingBarType, no part of this type: type
PredefinedType: MAIN; NominalDiameter: 0.016 m; CrossSectionArea: 0.00020106 m2; BarLength: 8.02121 m; Material: Steel

# IfcReinforcingBarType, no part of this type: type
PredefinedType: LIGATURE; NominalDiameter: 0.008 m; CrossSectionArea: 0.000050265 m2; BarLength: 2.42679 m; Material: Steel

# IfcReinforcingBarType, no part of this type: type
PredefinedType: MAIN; NominalDiameter: 0.016 m; CrossSectionArea: 0.00020106 m2; BarLength: 6.22121 m; Material: Steel

# IfcReinforcingBarType, no part of this type: type
PredefinedType: LIGATURE; NominalDiameter: 0.008 m; CrossSectionArea: 0.000050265 m2; BarLength: 2.42679 m; Material: Steel

# IfcReinforcingBarType, no part of this type: type
PredefinedType: MAIN; NominalDiameter: 0.016 m; CrossSectionArea: 0.00020106 m2; BarLength: 8.92122 m; Material: Steel

# IfcReinforcingBarType, no part of this type: type
PredefinedType: LIGATURE; NominalDiameter: 0.008 m; CrossSectionArea: 0.000050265 m2; BarLength: 2.42679 m; Material: Steel

# IfcReinforcingBarType, no part of this type: type
PredefinedType: MAIN; NominalDiameter: 0.016 m; CrossSectionArea: 0.00020106 m2; BarLength: 4.72121 m; Material: Steel

# IfcReinforcingBarType, no part of this type: type
PredefinedType: LIGATURE; NominalDiameter: 0.008 m; CrossSectionArea: 0.000050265 m2; BarLength: 2.42679 m; Material: Steel

# IfcReinforcingBarType, no part of this type: type
PredefinedType: MAIN; NominalDiameter: 0.016 m; CrossSectionArea: 0.00020106 m2; BarLength: 5.48642 m; Material: Steel

# IfcReinforcingBarType, no part of this type: type
PredefinedType: MAIN; NominalDiameter: 0.016 m; CrossSectionArea: 0.00020106 m2; BarLength: 11.2864 m; Material: Steel

# IfcReinforcingBarType, no part of this type: type
PredefinedType: LIGATURE; NominalDiameter: 0.008 m; CrossSectionArea: 0.000050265 m2; BarLength: 2.42679 m; Material: Steel

# IfcReinforcingBarType, no part of this type: type
PredefinedType: MAIN; NominalDiameter: 0.016 m; CrossSectionArea: 0.00020106 m2; BarLength: 5.49561 m; Material: Steel

# IfcReinforcingBarType, no part of this type: type
PredefinedType: MAIN; NominalDiameter: 0.016 m; CrossSectionArea: 0.00020106 m2; BarLength: 11.4956 m; Material: Steel

# IfcReinforcingBarType, no part of this type: type
PredefinedType: MAIN; NominalDiameter: 0.016 m; CrossSectionArea: 0.00020106 m2; BarLength: 6.49561 m; Material: Steel

# IfcReinforcingBarType, no part of this type: type
PredefinedType: LIGATURE; NominalDiameter: 0.008 m; CrossSectionArea: 0.000050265 m2; BarLength: 2.42679 m; Material: Steel

# IfcReinforcingBarType, no part of this type: type
PredefinedType: MAIN; NominalDiameter: 0.016 m; CrossSectionArea: 0.00020106 m2; BarLength: 11.3712 m; Material: Steel

# IfcReinforcingBarType, no part of this type: type
PredefinedType: LIGATURE; NominalDiameter: 0.008 m; CrossSectionArea: 0.000050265 m2; BarLength: 1.9268 m; Material: Steel

# IfcReinforcingBarType, no part of this type: type
PredefinedType: LIGATURE; NominalDiameter: 0.008 m; CrossSectionArea: 0.000050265 m2; BarLength: 2.32679 m; Material: Steel

# IfcReinforcingBarType, no part of this type: type
PredefinedType: MAIN; NominalDiameter: 0.014 m; CrossSectionArea: 0.00015394 m2; BarLength: 3.90992 m; Material: Steel

# IfcReinforcingBarType, no part of this type: type
PredefinedType: MAIN; NominalDiameter: 0.014 m; CrossSectionArea: 0.00015394 m2; BarLength: 3.89517 m; Material: Steel

# IfcReinforcingBarType, no part of this type: type
PredefinedType: MAIN; NominalDiameter: 0.014 m; CrossSectionArea: 0.00015394 m2; BarLength: 0.833931 m; Material: Steel

# IfcReinforcingBarType, no part of this type: type
PredefinedType: LIGATURE; NominalDiameter: 0.008 m; CrossSectionArea: 0.000050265 m2; BarLength: 1.9268 m; Material: Steel

# IfcReinforcingBarType, no part of this type: type
PredefinedType: MAIN; NominalDiameter: 0.014 m; CrossSectionArea: 0.00015394 m2; BarLength: 3.47578 m; Material: Steel

# IfcReinforcingBarType, no part of this type: type
PredefinedType: MAIN; NominalDiameter: 0.014 m; CrossSectionArea: 0.00015394 m2; BarLength: 3.56941 m; Material: Steel

# IfcReinforcingBarType, no part of this type: type
PredefinedType: MAIN; NominalDiameter: 0.014 m; CrossSectionArea: 0.00015394 m2; BarLength: 1.28074 m; Material: Steel

# IfcReinforcingBarType, no part of this type: type
PredefinedType: LIGATURE; NominalDiameter: 0.008 m; CrossSectionArea: 0.000050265 m2; BarLength: 1.9268 m; Material: Steel

# IfcReinforcingBarType, no part of this type: type
PredefinedType: LIGATURE; NominalDiameter: 0.008 m; CrossSectionArea: 0.000050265 m2; BarLength: 2.32679 m; Material: Steel

# IfcReinforcingBarType, no part of this type: type
PredefinedType: MAIN; NominalDiameter: 0.014 m; CrossSectionArea: 0.00015394 m2; BarLength: 4.04502 m; Material: Steel

# IfcReinforcingBarType, no part of this type: type
PredefinedType: MAIN; NominalDiameter: 0.014 m; CrossSectionArea: 0.00015394 m2; BarLength: 4.02817 m; Material: Steel

# IfcReinforcingBarType, no part of this type: type
PredefinedType: MAIN; NominalDiameter: 0.014 m; CrossSectionArea: 0.00015394 m2; BarLength: 0.829243 m; Material: Steel

# IfcReinforcingBarType, no part of this type: type
PredefinedType: LIGATURE; NominalDiameter: 0.008 m; CrossSectionArea: 0.000050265 m2; BarLength: 1.9268 m; Material: Steel

# IfcReinforcingBarType, no part of this type: type
PredefinedType: MAIN; NominalDiameter: 0.014 m; CrossSectionArea: 0.00015394 m2; BarLength: 3.56722 m; Material: Steel

# IfcReinforcingBarType, no part of this type: type
PredefinedType: MAIN; NominalDiameter: 0.014 m; CrossSectionArea: 0.00015394 m2; BarLength: 3.6688 m; Material: Steel

# IfcReinforcingBarType, no part of this type: type
PredefinedType: MAIN; NominalDiameter: 0.014 m; CrossSectionArea: 0.00015394 m2; BarLength: 1.27728 m; Material: Steel

# Material: Calcestruzzo
Calcestruzzo - Mass Density: 2500; Poisson Ratio: 0.1; Shear Modulus: 1300000000; Thermal Expansion Coefficient: 0.00001; Young Modulus: 3000000000

# Material: Calcestruzzo
Calcestruzzo - Mass Density: 2500; Poisson Ratio: 0.1; Shear Modulus: 1300000000; Thermal Expansion Coefficient: 0.00001; Young Modulus: 3000000000

# Material: Calcestruzzo
Calcestruzzo - Mass Density: 2500; Poisson Ratio: 0.1; Shear Modulus: 1300000000; Thermal Expansion Coefficient: 0.00001; Young Modulus: 3000000000

# Material: Calcestruzzo
Calcestruzzo - Mass Density: 2500; Poisson Ratio: 0.1; Shear Modulus: 1300000000; Thermal Expansion Coefficient: 0.00001; Young Modulus: 3000000000

# Material: Calcestruzzo
Calcestruzzo - Mass Density: 2500; Poisson Ratio: 0.1; Shear Modulus: 1300000000; Thermal Expansion Coefficient: 0.00001; Young Modulus: 3000000000

# Material: Calcestruzzo
Calcestruzzo - Mass Density: 2500; Poisson Ratio: 0.1; Shear Modulus: 1300000000; Thermal Expansion Coefficient: 0.00001; Young Modulus: 3000000000

# Material: Calcestruzzo
Calcestruzzo - Mass Density: 2500; Poisson Ratio: 0.1; Shear Modulus: 1300000000; Thermal Expansion Coefficient: 0.00001; Young Modulus: 3000000000

# Material: Calcestruzzo
Calcestruzzo - Mass Density: 2500; Poisson Ratio: 0.1; Shear Modulus: 1300000000; Thermal Expansion Coefficient: 0.00001; Young Modulus: 3000000000

# Material: Calcestruzzo
Calcestruzzo - Mass Density: 2500; Poisson Ratio: 0.1; Shear Modulus: 1300000000; Thermal Expansion Coefficient: 0.00001; Young Modulus: 3000000000

# Material: Calcestruzzo
Calcestruzzo - Mass Density: 2500; Poisson Ratio: 0.1; Shear Modulus: 1300000000; Thermal Expansion Coefficient: 0.00001; Young Modulus: 3000000000

# Material: Calcestruzzo
Calcestruzzo - Mass Density: 2500; Poisson Ratio: 0.1; Shear Modulus: 1300000000; Thermal Expansion Coefficient: 0.00001; Young Modulus: 3000000000

# Material: Calcestruzzo
Calcestruzzo - Mass Density: 2500; Poisson Ratio: 0.1; Shear Modulus: 1300000000; Thermal Expansion Coefficient: 0.00001; Young Modulus: 3000000000

# Material: Calcestruzzo
Calcestruzzo - Mass Density: 2500; Poisson Ratio: 0.1; Shear Modulus: 1300000000; Thermal Expansion Coefficient: 0.00001; Young Modulus: 3000000000

# Material: Calcestruzzo
Calcestruzzo - Mass Density: 2500; Poisson Ratio: 0.1; Shear Modulus: 1300000000; Thermal Expansion Coefficient: 0.00001; Young Modulus: 3000000000

# Material: Calcestruzzo
Calcestruzzo - Mass Density: 2500; Poisson Ratio: 0.1; Shear Modulus: 1300000000; Thermal Expansion Coefficient: 0.00001; Young Modulus: 3000000000

# Material: Calcestruzzo
Calcestruzzo - Mass Density: 2500; Poisson Ratio: 0.1; Shear Modulus: 1300000000; Thermal Expansion Coefficient: 0.00001; Young Modulus: 3000000000

# Material: Calcestruzzo
Calcestruzzo - Mass Density: 2500; Poisson Ratio: 0.1; Shear Modulus: 1300000000; Thermal Expansion Coefficient: 0.00001; Young Modulus: 3000000000

# Material: Calcestruzzo
Calcestruzzo - Mass Density: 2500; Poisson Ratio: 0.1; Shear Modulus: 1300000000; Thermal Expansion Coefficient: 0.00001; Young Modulus: 3000000000

# Material: Calcestruzzo
Calcestruzzo - Mass Density: 2500; Poisson Ratio: 0.1; Shear Modulus: 1300000000; Thermal Expansion Coefficient: 0.00001; Young Modulus: 3000000000

# Material: Calcestruzzo
Calcestruzzo - Mass Density: 2500; Poisson Ratio: 0.1; Shear Modulus: 1300000000; Thermal Expansion Coefficient: 0.00001; Young Modulus: 3000000000

# Material: Calcestruzzo
Calcestruzzo - Mass Density: 2500; Poisson Ratio: 0.1; Shear Modulus: 1300000000; Thermal Expansion Coefficient: 0.00001; Young Modulus: 3000000000

# Material: Calcestruzzo
Calcestruzzo - Mass Density: 2500; Poisson Ratio: 0.1; Shear Modulus: 1300000000; Thermal Expansion Coefficient: 0.00001; Young Modulus: 3000000000

# Material: Calcestruzzo
Calcestruzzo - Mass Density: 2500; Poisson Ratio: 0.1; Shear Modulus: 1300000000; Thermal Expansion Coefficient: 0.00001; Young Modulus: 3000000000

# Material: Calcestruzzo
Calcestruzzo - Mass Density: 2500; Poisson Ratio: 0.1; Shear Modulus: 1300000000; Thermal Expansion Coefficient: 0.00001; Young Modulus: 3000000000

# Material: Calcestruzzo
Calcestruzzo - Mass Density: 2500; Poisson Ratio: 0.1; Shear Modulus: 1300000000; Thermal Expansion Coefficient: 0.00001; Young Modulus: 3000000000

# Material: Calcestruzzo
Calcestruzzo - Mass Density: 2500; Poisson Ratio: 0.1; Shear Modulus: 1300000000; Thermal Expansion Coefficient: 0.00001; Young Modulus: 3000000000

# Material: Calcestruzzo
Calcestruzzo - Mass Density: 2500; Poisson Ratio: 0.1; Shear Modulus: 1300000000; Thermal Expansion Coefficient: 0.00001; Young Modulus: 3000000000

# Material: Calcestruzzo
Calcestruzzo - Mass Density: 2500; Poisson Ratio: 0.1; Shear Modulus: 1300000000; Thermal Expansion Coefficient: 0.00001; Young Modulus: 3000000000

# Material: Calcestruzzo
Calcestruzzo - Mass Density: 2500; Poisson Ratio: 0.1; Shear Modulus: 1300000000; Thermal Expansion Coefficient: 0.00001; Young Modulus: 3000000000

# Material: Calcestruzzo
Calcestruzzo - Mass Density: 2500; Poisson Ratio: 0.1; Shear Modulus: 1300000000; Thermal Expansion Coefficient: 0.00001; Young Modulus: 3000000000

# Material: Calcestruzzo
Calcestruzzo - Mass Density: 2500; Poisson Ratio: 0.1; Shear Modulus: 1300000000; Thermal Expansion Coefficient: 0.00001; Young Modulus: 3000000000

# Material: Calcestruzzo
Calcestruzzo - Mass Density: 2500; Poisson Ratio: 0.1; Shear Modulus: 1300000000; Thermal Expansion Coefficient: 0.00001; Young Modulus: 3000000000

# Material: Calcestruzzo
Calcestruzzo - Mass Density: 2500; Poisson Ratio: 0.1; Shear Modulus: 1300000000; Thermal Expansion Coefficient: 0.00001; Young Modulus: 3000000000

# Material: Calcestruzzo
Calcestruzzo - Mass Density: 2500; Poisson Ratio: 0.1; Shear Modulus: 1300000000; Thermal Expansion Coefficient: 0.00001; Young Modulus: 3000000000

# Material: Calcestruzzo
Calcestruzzo - Mass Density: 2500; Poisson Ratio: 0.1; Shear Modulus: 1300000000; Thermal Expansion Coefficient: 0.00001; Young Modulus: 3000000000

# Material: Calcestruzzo
Calcestruzzo - Mass Density: 2500; Poisson Ratio: 0.1; Shear Modulus: 1300000000; Thermal Expansion Coefficient: 0.00001; Young Modulus: 3000000000

# Material: Calcestruzzo
Calcestruzzo - Mass Density: 2500; Poisson Ratio: 0.1; Shear Modulus: 1300000000; Thermal Expansion Coefficient: 0.00001; Young Modulus: 3000000000

# Material: Calcestruzzo
Calcestruzzo - Mass Density: 2500; Poisson Ratio: 0.1; Shear Modulus: 1300000000; Thermal Expansion Coefficient: 0.00001; Young Modulus: 3000000000

# Material: Calcestruzzo
Calcestruzzo - Mass Density: 2500; Poisson Ratio: 0.1; Shear Modulus: 1300000000; Thermal Expansion Coefficient: 0.00001; Young Modulus: 3000000000

# Material: Calcestruzzo
Calcestruzzo - Mass Density: 2500; Poisson Ratio: 0.1; Shear Modulus: 1300000000; Thermal Expansion Coefficient: 0.00001; Young Modulus: 3000000000

# Material: Calcestruzzo
Calcestruzzo - Mass Density: 2500; Poisson Ratio: 0.1; Shear Modulus: 1300000000; Thermal Expansion Coefficient: 0.00001; Young Modulus: 3000000000

# Material: Calcestruzzo
Calcestruzzo - Mass Density: 2500; Poisson Ratio: 0.1; Shear Modulus: 1300000000; Thermal Expansion Coefficient: 0.00001; Young Modulus: 3000000000

# Material: Calcestruzzo
Calcestruzzo - Mass Density: 2500; Poisson Ratio: 0.1; Shear Modulus: 1300000000; Thermal Expansion Coefficient: 0.00001; Young Modulus: 3000000000

# Material: Calcestruzzo
Calcestruzzo - Mass Density: 2500; Poisson Ratio: 0.1; Shear Modulus: 1300000000; Thermal Expansion Coefficient: 0.00001; Young Modulus: 3000000000

# Material: Calcestruzzo
Calcestruzzo - Mass Density: 2500; Poisson Ratio: 0.1; Shear Modulus: 1300000000; Thermal Expansion Coefficient: 0.00001; Young Modulus: 3000000000

# Material: Calcestruzzo
Calcestruzzo - Mass Density: 2500; Poisson Ratio: 0.1; Shear Modulus: 1300000000; Thermal Expansion Coefficient: 0.00001; Young Modulus: 3000000000

# Material: Calcestruzzo
Calcestruzzo - Mass Density: 2500; Poisson Ratio: 0.1; Shear Modulus: 1300000000; Thermal Expansion Coefficient: 0.00001; Young Modulus: 3000000000

# Material: Calcestruzzo
Calcestruzzo - Mass Density: 2500; Poisson Ratio: 0.1; Shear Modulus: 1300000000; Thermal Expansion Coefficient: 0.00001; Young Modulus: 3000000000

# Material: Calcestruzzo
Calcestruzzo - Mass Density: 2500; Poisson Ratio: 0.1; Shear Modulus: 1300000000; Thermal Expansion Coefficient: 0.00001; Young Modulus: 3000000000

# Material: Calcestruzzo
Calcestruzzo - Mass Density: 2500; Poisson Ratio: 0.1; Shear Modulus: 1300000000; Thermal Expansion Coefficient: 0.00001; Young Modulus: 3000000000

# Material: Calcestruzzo
Calcestruzzo - Mass Density: 2500; Poisson Ratio: 0.1; Shear Modulus: 1300000000; Thermal Expansion Coefficient: 0.00001; Young Modulus: 3000000000

# Material: Calcestruzzo
Calcestruzzo - Mass Density: 2500; Poisson Ratio: 0.1; Shear Modulus: 1300000000; Thermal Expansion Coefficient: 0.00001; Young Modulus: 3000000000

# Material: Calcestruzzo
Calcestruzzo - Mass Density: 2500; Poisson Ratio: 0.1; Shear Modulus: 1300000000; Thermal Expansion Coefficient: 0.00001; Young Modulus: 3000000000

# Material: Calcestruzzo
Calcestruzzo - Mass Density: 2500; Poisson Ratio: 0.1; Shear Modulus: 1300000000; Thermal Expansion Coefficient: 0.00001; Young Modulus: 3000000000

# Material: Calcestruzzo
Calcestruzzo - Mass Density: 2500; Poisson Ratio: 0.1; Shear Modulus: 1300000000; Thermal Expansion Coefficient: 0.00001; Young Modulus: 3000000000

# Material: Calcestruzzo
Calcestruzzo - Mass Density: 2500; Poisson Ratio: 0.1; Shear Modulus: 1300000000; Thermal Expansion Coefficient: 0.00001; Young Modulus: 3000000000

# Material: Calcestruzzo
Calcestruzzo - Mass Density: 2500; Poisson Ratio: 0.1; Shear Modulus: 1300000000; Thermal Expansion Coefficient: 0.00001; Young Modulus: 3000000000

# Material: Calcestruzzo
Calcestruzzo - Mass Density: 2500; Poisson Ratio: 0.1; Shear Modulus: 1300000000; Thermal Expansion Coefficient: 0.00001; Young Modulus: 3000000000

# Material: Calcestruzzo
Calcestruzzo - Mass Density: 2500; Poisson Ratio: 0.1; Shear Modulus: 1300000000; Thermal Expansion Coefficient: 0.00001; Young Modulus: 3000000000

# Material: Calcestruzzo
Calcestruzzo - Mass Density: 2500; Poisson Ratio: 0.1; Shear Modulus: 1300000000; Thermal Expansion Coefficient: 0.00001; Young Modulus: 3000000000

# Material: Calcestruzzo
Calcestruzzo - Mass Density: 2500; Poisson Ratio: 0.1; Shear Modulus: 1300000000; Thermal Expansion Coefficient: 0.00001; Young Modulus: 3000000000

# Material: Calcestruzzo
Calcestruzzo - Mass Density: 2500; Poisson Ratio: 0.1; Shear Modulus: 1300000000; Thermal Expansion Coefficient: 0.00001; Young Modulus: 3000000000

# Material: Calcestruzzo
Calcestruzzo - Mass Density: 2500; Poisson Ratio: 0.1; Shear Modulus: 1300000000; Thermal Expansion Coefficient: 0.00001; Young Modulus: 3000000000

# Material: Calcestruzzo
Calcestruzzo - Mass Density: 2500; Poisson Ratio: 0.1; Shear Modulus: 1300000000; Thermal Expansion Coefficient: 0.00001; Young Modulus: 3000000000

# Material: Calcestruzzo
Calcestruzzo - Mass Density: 2500; Poisson Ratio: 0.1; Shear Modulus: 1300000000; Thermal Expansion Coefficient: 0.00001; Young Modulus: 3000000000

# Material: Calcestruzzo
Calcestruzzo - Mass Density: 2500; Poisson Ratio: 0.1; Shear Modulus: 1300000000; Thermal Expansion Coefficient: 0.00001; Young Modulus: 3000000000

# Material: Calcestruzzo
Calcestruzzo - Mass Density: 2500; Poisson Ratio: 0.1; Shear Modulus: 1300000000; Thermal Expansion Coefficient: 0.00001; Young Modulus: 3000000000

# Material: Calcestruzzo
Calcestruzzo - Mass Density: 2500; Poisson Ratio: 0.1; Shear Modulus: 1300000000; Thermal Expansion Coefficient: 0.00001; Young Modulus: 3000000000

# Material: Calcestruzzo
Calcestruzzo - Mass Density: 2500; Poisson Ratio: 0.1; Shear Modulus: 1300000000; Thermal Expansion Coefficient: 0.00001; Young Modulus: 3000000000

# Material: Calcestruzzo
Calcestruzzo - Mass Density: 2500; Poisson Ratio: 0.1; Shear Modulus: 1300000000; Thermal Expansion Coefficient: 0.00001; Young Modulus: 3000000000

# Material: Calcestruzzo
Calcestruzzo - Mass Density: 2500; Poisson Ratio: 0.1; Shear Modulus: 1300000000; Thermal Expansion Coefficient: 0.00001; Young Modulus: 3000000000

# Material: Calcestruzzo
Calcestruzzo - Mass Density: 2500; Poisson Ratio: 0.1; Shear Modulus: 1300000000; Thermal Expansion Coefficient: 0.00001; Young Modulus: 3000000000

# Material: Calcestruzzo
